# Generated by innovus_enablement/scripts/gen_innovus_lef.py from ../i3dPDK_NS3K/BE/i3dPDK_NS3K_5T_0V7_27C.lef
# Read AFTER the matching i3dPDK_NS3K_<N>T_tech.lef.
VERSION 5.8 ;
BUSBITCHARS "[]" ;
DIVIDERCHAR "/" ;





























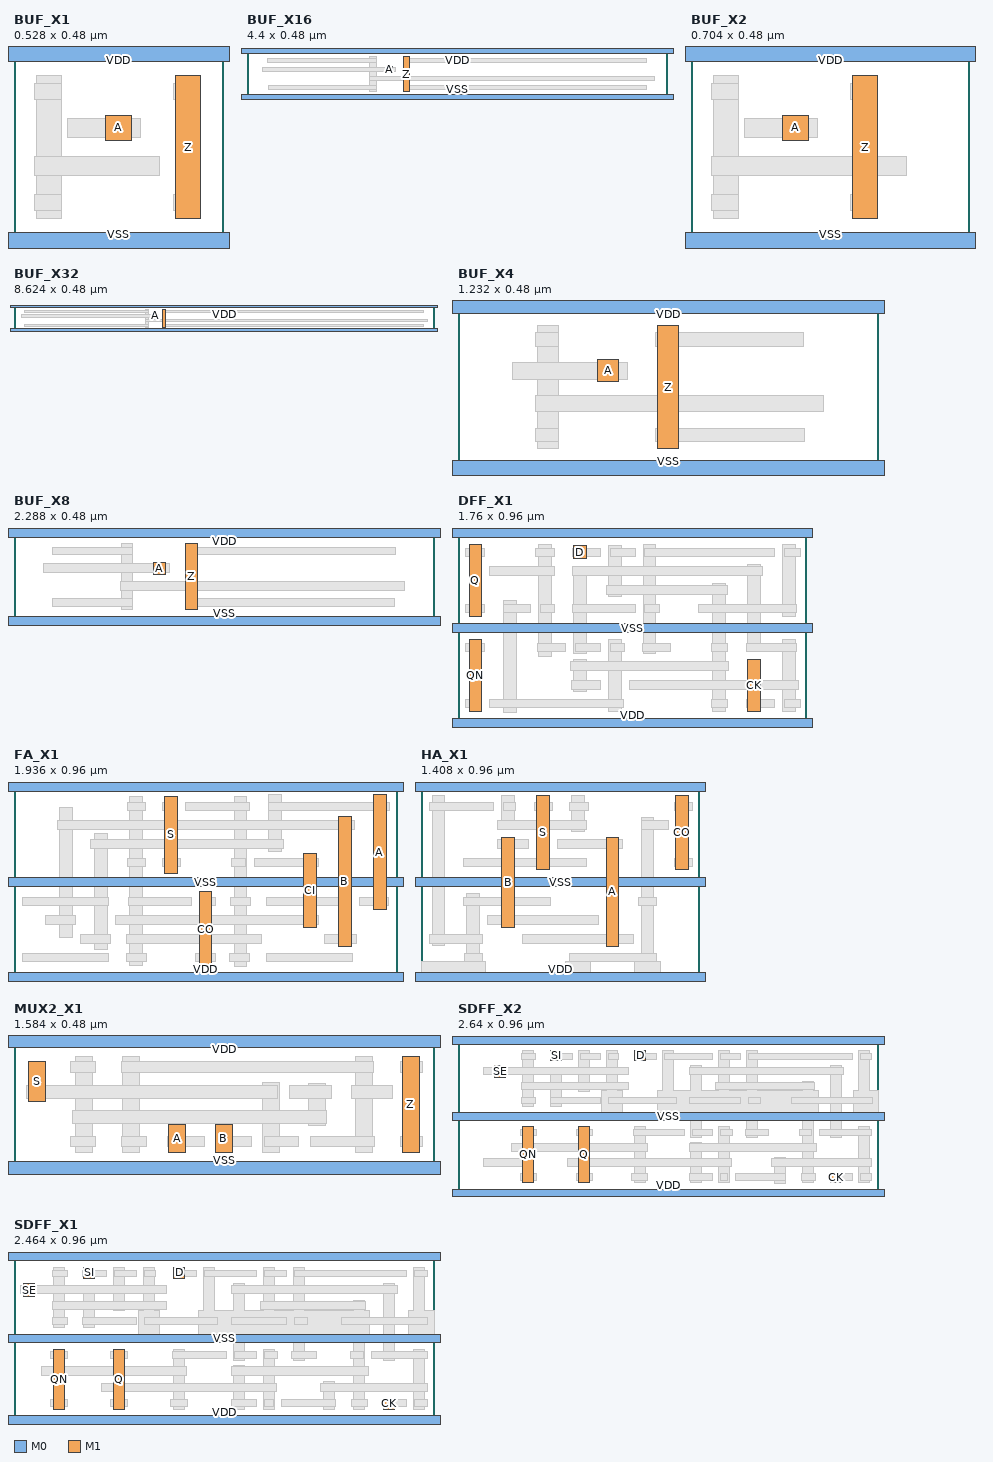
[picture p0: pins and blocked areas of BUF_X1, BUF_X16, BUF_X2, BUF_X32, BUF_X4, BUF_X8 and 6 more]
MACRO BUF_X1
  CLASS CORE ;
  ORIGIN 0 0 ;
  FOREIGN BUF_X1 0 0 ;
  SYMMETRY X Y ;
  SITE i3d_nsfet3nm ;
  SIZE 0.5280 BY 0.4800 ;
  PIN VDD
    DIRECTION INOUT ;
    USE POWER ;
    PORT
      LAYER M0 ;
        RECT -0.0640 0.4560 0.5920 0.5040 ;
    END
  END VDD
  PIN VSS
    DIRECTION INOUT ;
    USE GROUND ;
    PORT
      LAYER M0 ;
        RECT -0.0640 -0.0240 0.5920 0.0240 ;
    END
  END VSS
  PIN A
    DIRECTION INPUT ;
    USE SIGNAL ;
    PORT
      LAYER M1 ;
        RECT 0.2320 0.2560 0.2960 0.3200 ;
    END
  END A
  PIN Z
    DIRECTION OUTPUT ;
    USE SIGNAL ;
    PORT
      LAYER M1 ;
        RECT 0.4080 0.0600 0.4720 0.4200 ;
    END
  END Z
  OBS
    LAYER M1 DESIGNRULEWIDTH 0 ;
      RECT 0.0560 0.0600 0.1200 0.4200 ;
    LAYER M0 DESIGNRULEWIDTH 0 ;
      RECT 0.4040 0.0800 0.4720 0.1200 ;
      RECT 0.0520 0.0800 0.1200 0.1200 ;
      RECT 0.0520 0.1680 0.3680 0.2160 ;
      RECT 0.1360 0.2640 0.3200 0.3120 ;
      RECT 0.4040 0.3600 0.4720 0.4000 ;
      RECT 0.0520 0.3600 0.1200 0.4000 ;
  END
END BUF_X1

MACRO BUF_X16
  CLASS CORE ;
  ORIGIN 0 0 ;
  FOREIGN BUF_X16 0 0 ;
  SYMMETRY X Y ;
  SITE i3d_nsfet3nm ;
  SIZE 4.4000 BY 0.4800 ;
  PIN VDD
    DIRECTION INOUT ;
    USE POWER ;
    PORT
      LAYER M0 ;
        RECT -0.0640 0.4560 4.4640 0.5040 ;
    END
  END VDD
  PIN VSS
    DIRECTION INOUT ;
    USE GROUND ;
    PORT
      LAYER M0 ;
        RECT -0.0640 -0.0240 4.4640 0.0240 ;
    END
  END VSS
  PIN A
    DIRECTION INPUT ;
    USE SIGNAL ;
    PORT
      LAYER M1 ;
        RECT 1.4640 0.2560 1.5280 0.3200 ;
    END
  END A
  PIN Z
    DIRECTION OUTPUT ;
    USE SIGNAL ;
    PORT
      LAYER M1 ;
        RECT 1.6400 0.0600 1.7040 0.4200 ;
    END
  END Z
  OBS
    LAYER M1 DESIGNRULEWIDTH 0 ;
      RECT 1.2880 0.0600 1.3520 0.4200 ;
    LAYER M0 DESIGNRULEWIDTH 0 ;
      RECT 1.6360 0.0800 4.1840 0.1200 ;
      RECT 0.2240 0.0800 1.3520 0.1200 ;
      RECT 1.2840 0.1680 4.2640 0.2160 ;
      RECT 0.1600 0.2640 1.5520 0.3120 ;
      RECT 1.6360 0.3600 4.1880 0.4000 ;
      RECT 0.2120 0.3600 1.3520 0.4000 ;
  END
END BUF_X16

MACRO BUF_X2
  CLASS CORE ;
  ORIGIN 0 0 ;
  FOREIGN BUF_X2 0 0 ;
  SYMMETRY X Y ;
  SITE i3d_nsfet3nm ;
  SIZE 0.7040 BY 0.4800 ;
  PIN VDD
    DIRECTION INOUT ;
    USE POWER ;
    PORT
      LAYER M0 ;
        RECT -0.0640 0.4560 0.7680 0.5040 ;
    END
  END VDD
  PIN VSS
    DIRECTION INOUT ;
    USE GROUND ;
    PORT
      LAYER M0 ;
        RECT -0.0640 -0.0240 0.7680 0.0240 ;
    END
  END VSS
  PIN A
    DIRECTION INPUT ;
    USE SIGNAL ;
    PORT
      LAYER M1 ;
        RECT 0.2320 0.2560 0.2960 0.3200 ;
    END
  END A
  PIN Z
    DIRECTION OUTPUT ;
    USE SIGNAL ;
    PORT
      LAYER M1 ;
        RECT 0.4080 0.0600 0.4720 0.4200 ;
    END
  END Z
  OBS
    LAYER M1 DESIGNRULEWIDTH 0 ;
      RECT 0.0560 0.0600 0.1200 0.4200 ;
    LAYER M0 DESIGNRULEWIDTH 0 ;
      RECT 0.4040 0.0800 0.4720 0.1200 ;
      RECT 0.0520 0.0800 0.1200 0.1200 ;
      RECT 0.0520 0.1680 0.5440 0.2160 ;
      RECT 0.1360 0.2640 0.3200 0.3120 ;
      RECT 0.4040 0.3600 0.4720 0.4000 ;
      RECT 0.0520 0.3600 0.1200 0.4000 ;
  END
END BUF_X2

MACRO BUF_X32
  CLASS CORE ;
  ORIGIN 0 0 ;
  FOREIGN BUF_X32 0 0 ;
  SYMMETRY X Y ;
  SITE i3d_nsfet3nm ;
  SIZE 8.6240 BY 0.4800 ;
  PIN VDD
    DIRECTION INOUT ;
    USE POWER ;
    PORT
      LAYER M0 ;
        RECT -0.0640 0.4560 8.6880 0.5040 ;
    END
  END VDD
  PIN VSS
    DIRECTION INOUT ;
    USE GROUND ;
    PORT
      LAYER M0 ;
        RECT -0.0640 -0.0240 8.6880 0.0240 ;
    END
  END VSS
  PIN Z
    DIRECTION OUTPUT ;
    USE SIGNAL ;
    PORT
      LAYER M1 ;
        RECT 3.0480 0.0600 3.1120 0.4200 ;
    END
  END Z
  PIN A
    DIRECTION INPUT ;
    USE SIGNAL ;
    PORT
      LAYER M1 ;
        RECT 2.8720 0.2560 2.9360 0.3200 ;
    END
  END A
  OBS
    LAYER M1 DESIGNRULEWIDTH 0 ;
      RECT 2.6960 0.0600 2.7600 0.4200 ;
    LAYER M0 DESIGNRULEWIDTH 0 ;
      RECT 3.0440 0.0800 8.4160 0.1200 ;
      RECT 0.2200 0.0800 2.7600 0.1200 ;
      RECT 2.6920 0.1680 8.4920 0.2160 ;
      RECT 0.1560 0.2640 2.9600 0.3120 ;
      RECT 3.0440 0.3600 8.4040 0.4000 ;
      RECT 0.2120 0.3600 2.7600 0.4000 ;
  END
END BUF_X32

MACRO BUF_X4
  CLASS CORE ;
  ORIGIN 0 0 ;
  FOREIGN BUF_X4 0 0 ;
  SYMMETRY X Y ;
  SITE i3d_nsfet3nm ;
  SIZE 1.2320 BY 0.4800 ;
  PIN VDD
    DIRECTION INOUT ;
    USE POWER ;
    PORT
      LAYER M0 ;
        RECT -0.0640 0.4560 1.2960 0.5040 ;
    END
  END VDD
  PIN VSS
    DIRECTION INOUT ;
    USE GROUND ;
    PORT
      LAYER M0 ;
        RECT -0.0640 -0.0240 1.2960 0.0240 ;
    END
  END VSS
  PIN A
    DIRECTION INPUT ;
    USE SIGNAL ;
    PORT
      LAYER M1 ;
        RECT 0.4080 0.2560 0.4720 0.3200 ;
    END
  END A
  PIN Z
    DIRECTION OUTPUT ;
    USE SIGNAL ;
    PORT
      LAYER M1 ;
        RECT 0.5840 0.0600 0.6480 0.4200 ;
    END
  END Z
  OBS
    LAYER M1 DESIGNRULEWIDTH 0 ;
      RECT 0.2320 0.0600 0.2960 0.4200 ;
    LAYER M0 DESIGNRULEWIDTH 0 ;
      RECT 0.5800 0.0800 1.0160 0.1200 ;
      RECT 0.2280 0.0800 0.2960 0.1200 ;
      RECT 0.2280 0.1680 1.0720 0.2160 ;
      RECT 0.1600 0.2640 0.4960 0.3120 ;
      RECT 0.5800 0.3600 1.0120 0.4000 ;
      RECT 0.2280 0.3600 0.2960 0.4000 ;
  END
END BUF_X4

MACRO BUF_X8
  CLASS CORE ;
  ORIGIN 0 0 ;
  FOREIGN BUF_X8 0 0 ;
  SYMMETRY X Y ;
  SITE i3d_nsfet3nm ;
  SIZE 2.2880 BY 0.4800 ;
  PIN VDD
    DIRECTION INOUT ;
    USE POWER ;
    PORT
      LAYER M0 ;
        RECT -0.0640 0.4560 2.3520 0.5040 ;
    END
  END VDD
  PIN VSS
    DIRECTION INOUT ;
    USE GROUND ;
    PORT
      LAYER M0 ;
        RECT -0.0640 -0.0240 2.3520 0.0240 ;
    END
  END VSS
  PIN A
    DIRECTION INPUT ;
    USE SIGNAL ;
    PORT
      LAYER M1 ;
        RECT 0.7600 0.2560 0.8240 0.3200 ;
    END
  END A
  PIN Z
    DIRECTION OUTPUT ;
    USE SIGNAL ;
    PORT
      LAYER M1 ;
        RECT 0.9360 0.0600 1.0000 0.4200 ;
    END
  END Z
  OBS
    LAYER M1 DESIGNRULEWIDTH 0 ;
      RECT 0.5840 0.0600 0.6480 0.4200 ;
    LAYER M0 DESIGNRULEWIDTH 0 ;
      RECT 0.9320 0.0800 2.0720 0.1200 ;
      RECT 0.2080 0.0800 0.6480 0.1200 ;
      RECT 0.5800 0.1680 2.1280 0.2160 ;
      RECT 0.1600 0.2640 0.8480 0.3120 ;
      RECT 0.9320 0.3600 2.0760 0.4000 ;
      RECT 0.2080 0.3600 0.6480 0.4000 ;
  END
END BUF_X8

MACRO DFF_X1
  CLASS CORE ;
  ORIGIN 0 0 ;
  FOREIGN DFF_X1 0 0 ;
  SYMMETRY X Y ;
  SITE i3d_nsfet3nm_2H_VDD ;
  SIZE 1.7600 BY 0.9600 ;
  PIN Q
    DIRECTION OUTPUT ;
    USE SIGNAL ;
    PORT
      LAYER M1 ;
        RECT 0.0560 0.5400 0.1200 0.9000 ;
    END
  END Q
  PIN VDD
    DIRECTION INOUT ;
    USE POWER ;
    PORT
      LAYER M0 ;
        RECT -0.0640 0.9360 1.8240 0.9840 ;
        RECT -0.0640 -0.0240 1.8240 0.0240 ;
    END
  END VDD
  PIN VSS
    DIRECTION INOUT ;
    USE GROUND ;
    PORT
      LAYER M0 ;
        RECT -0.0640 0.4560 1.8240 0.5040 ;
    END
  END VSS
  PIN D
    DIRECTION INPUT ;
    USE SIGNAL ;
    PORT
      LAYER M1 ;
        RECT 0.5840 0.8320 0.6480 0.8960 ;
    END
  END D
  PIN QN
    DIRECTION OUTPUT ;
    USE SIGNAL ;
    PORT
      LAYER M1 ;
        RECT 0.0560 0.0600 0.1200 0.4200 ;
    END
  END QN
  PIN CK
    DIRECTION INPUT ;
    USE SIGNAL ;
    PORT
      LAYER M1 ;
        RECT 1.4640 0.0600 1.5280 0.3200 ;
    END
  END CK
  OBS
    LAYER M1 ;
      RECT 0.2320 0.0520 0.2960 0.6200 ;
      RECT 0.7600 0.0600 0.8240 0.4200 ;
      RECT 1.2880 0.0600 1.3520 0.7040 ;
      RECT 1.6400 0.0600 1.7040 0.4200 ;
      RECT 0.5840 0.1600 0.6480 0.3200 ;
      RECT 0.4080 0.3360 0.4720 0.9000 ;
      RECT 0.5840 0.3520 0.6480 0.7520 ;
      RECT 0.9360 0.3520 1.0000 0.9000 ;
      RECT 1.4640 0.4000 1.5280 0.8000 ;
      RECT 1.6400 0.5400 1.7040 0.9000 ;
      RECT 0.7600 0.6400 0.8240 0.8960 ;
    LAYER M0 ;
      RECT 0.0400 0.0800 0.1120 0.1200 ;
      RECT 0.1600 0.0800 0.8360 0.1200 ;
      RECT 1.2800 0.0800 1.3600 0.1200 ;
      RECT 1.4600 0.0800 1.6000 0.1200 ;
      RECT 1.6480 0.0800 1.7280 0.1200 ;
      RECT 0.5720 0.1680 0.7200 0.2160 ;
      RECT 0.8640 0.1680 1.7200 0.2160 ;
      RECT 0.5680 0.2640 1.3680 0.3120 ;
      RECT 0.0400 0.3600 0.1360 0.4000 ;
      RECT 0.4000 0.3600 0.5440 0.4000 ;
      RECT 0.5920 0.3600 0.7200 0.4000 ;
      RECT 0.7680 0.3600 0.8400 0.4000 ;
      RECT 0.9320 0.3600 1.0720 0.4000 ;
      RECT 1.2800 0.3600 1.3600 0.4000 ;
      RECT 1.4560 0.3600 1.7120 0.4000 ;
      RECT 0.0400 0.5600 0.1360 0.6000 ;
      RECT 0.2280 0.5600 0.3680 0.6000 ;
      RECT 0.4160 0.5600 0.4880 0.6000 ;
      RECT 0.5760 0.5600 0.8960 0.6000 ;
      RECT 0.9440 0.5600 1.0200 0.6000 ;
      RECT 1.2160 0.5600 1.7120 0.6000 ;
      RECT 0.7480 0.6480 1.3600 0.6960 ;
      RECT 0.1600 0.7440 0.4880 0.7920 ;
      RECT 0.5800 0.7440 1.5360 0.7920 ;
      RECT 0.0400 0.8400 0.1360 0.8800 ;
      RECT 0.3920 0.8400 0.4880 0.8800 ;
      RECT 0.5760 0.8400 0.7200 0.8800 ;
      RECT 0.7680 0.8400 0.8960 0.8800 ;
      RECT 0.9440 0.8400 1.6000 0.8800 ;
      RECT 1.6480 0.8400 1.7280 0.8800 ;
  END
END DFF_X1


MACRO FA_X1
  CLASS CORE ;
  ORIGIN 0 0 ;
  FOREIGN FA 0 0 ;
  SYMMETRY X Y ;
  SITE i3d_nsfet3nm_2H_VDD ;
  SIZE 1.9360 BY 0.9600 ;
  PIN VDD
    DIRECTION INOUT ;
    USE POWER ;
    PORT
      LAYER M0 ;
        RECT -0.0640 -0.0240 2.0000 0.0240 ;
        RECT -0.0640 0.9360 2.0000 0.9840 ;
    END
  END VDD
  PIN VSS
    DIRECTION INOUT ;
    USE GROUND ;
    PORT
      LAYER M0 ;
        RECT -0.0640 0.4560 2.0000 0.5040 ;
    END
  END VSS
  PIN CO
    DIRECTION OUTPUT ;
    USE SIGNAL ;
    PORT
      LAYER M1 ;
        RECT 0.9360 0.0520 1.0000 0.4320 ;
    END
  END CO
  PIN CI
    DIRECTION INPUT ;
    USE SIGNAL ;
    PORT
      LAYER M1 ;
        RECT 1.4640 0.2520 1.5280 0.6240 ;
    END
  END CI
  PIN A
    DIRECTION INPUT ;
    USE SIGNAL ;
    PORT
      LAYER M1 ;
        RECT 1.8160 0.3400 1.8800 0.9200 ;
    END
  END A
  PIN B
    DIRECTION INPUT ;
    USE SIGNAL ;
    PORT
      LAYER M1 ;
        RECT 1.6400 0.1560 1.7040 0.8120 ;
    END
  END B
  PIN S
    DIRECTION OUTPUT ;
    USE SIGNAL ;
    PORT
      LAYER M1 ;
        RECT 0.7600 0.5240 0.8240 0.9120 ;
    END
  END S
  OBS
    LAYER M1 DESIGNRULEWIDTH 0 ;
      RECT 1.1120 0.0520 1.1760 0.9120 ;
      RECT 0.5840 0.0560 0.6480 0.9120 ;
      RECT 0.4080 0.1400 0.4720 0.7240 ;
      RECT 0.2320 0.2000 0.2960 0.8560 ;
      RECT 1.2880 0.6360 1.3520 0.9200 ;
    LAYER M0 DESIGNRULEWIDTH 0 ;
      RECT 1.2760 0.0800 1.7080 0.1200 ;
      RECT 1.0880 0.0800 1.1880 0.1200 ;
      RECT 0.9160 0.0800 1.0160 0.1200 ;
      RECT 0.5680 0.0800 0.6680 0.1200 ;
      RECT 0.0440 0.0800 0.4760 0.1200 ;
      RECT 1.5680 0.1680 1.7280 0.2160 ;
      RECT 0.5680 0.1680 1.2480 0.2160 ;
      RECT 0.3360 0.1680 0.4880 0.2160 ;
      RECT 0.5120 0.2640 1.5360 0.3120 ;
      RECT 0.1600 0.2640 0.3120 0.3120 ;
      RECT 1.7440 0.3600 1.8920 0.4000 ;
      RECT 1.2760 0.3600 1.6960 0.4000 ;
      RECT 1.0960 0.3600 1.1960 0.4000 ;
      RECT 0.9440 0.3600 1.0160 0.4000 ;
      RECT 0.5760 0.3600 0.8960 0.4000 ;
      RECT 0.0440 0.3600 0.4760 0.4000 ;
      RECT 1.2160 0.5600 1.5360 0.6000 ;
      RECT 1.1000 0.5600 1.1680 0.6000 ;
      RECT 0.7480 0.5600 0.8400 0.6000 ;
      RECT 0.5720 0.5600 0.6640 0.6000 ;
      RECT 0.3880 0.6480 1.3600 0.6960 ;
      RECT 0.2200 0.7440 1.7200 0.7920 ;
      RECT 1.2840 0.8400 1.8960 0.8800 ;
      RECT 0.8640 0.8400 1.1920 0.8800 ;
      RECT 0.7480 0.8400 0.8160 0.8800 ;
      RECT 0.5720 0.8400 0.6640 0.8800 ;
  END
END FA_X1

MACRO HA_X1
  CLASS CORE ;
  ORIGIN 0 0 ;
  FOREIGN HA 0 0 ;
  SYMMETRY X Y ;
  SITE i3d_nsfet3nm_2H_VDD ;
  SIZE 1.4080 BY 0.9600 ;
  PIN VDD
    DIRECTION INOUT ;
    USE POWER ;
    PORT
      LAYER M0 ;
        RECT -0.0640 -0.0240 1.4720 0.0240 ;
        RECT -0.0640 0.9360 1.4720 0.9840 ;
    END
  END VDD
  PIN S
    DIRECTION OUTPUT ;
    USE SIGNAL ;
    PORT
      LAYER M1 ;
        RECT 0.5840 0.5440 0.6480 0.9160 ;
    END
  END S
  PIN B
    DIRECTION INPUT ;
    USE SIGNAL ;
    PORT
      LAYER M1 ;
        RECT 0.4080 0.2520 0.4720 0.7040 ;
    END
  END B
  PIN A
    DIRECTION INPUT ;
    USE SIGNAL ;
    PORT
      LAYER M1 ;
        RECT 0.9360 0.1560 1.0000 0.7040 ;
    END
  END A
  PIN VSS
    DIRECTION INOUT ;
    USE GROUND ;
    PORT
      LAYER M0 ;
        RECT -0.0640 0.4560 1.4720 0.5040 ;
    END
  END VSS
  PIN CO
    DIRECTION OUTPUT ;
    USE SIGNAL ;
    PORT
      LAYER M1 ;
        RECT 1.2880 0.5440 1.3520 0.9160 ;
    END
  END CO
  OBS
    LAYER M1 DESIGNRULEWIDTH 0 ;
      POLYGON 1.2080 0.0000 1.2080 0.0760 1.1760 0.0760 1.1760 0.8040 1.1120 0.8040 1.1120 0.0760 1.0800 0.0760 1.0800 0.0000 ;
      RECT 0.7280 0.0000 0.8560 0.0760 ;
      POLYGON 0.3280 0.0000 0.3280 0.0760 0.2960 0.0760 0.2960 0.4200 0.2320 0.4200 0.2320 0.0760 0.0000 0.0760 0.0000 0.0000 ;
      RECT 0.0560 0.1600 0.1200 0.9160 ;
      RECT 0.7600 0.7360 0.8240 0.9160 ;
      RECT 0.4080 0.7840 0.4720 0.9160 ;
    LAYER M0 DESIGNRULEWIDTH 0 ;
      RECT 0.7480 0.0800 1.1920 0.1200 ;
      RECT 0.2200 0.0800 0.3120 0.1200 ;
      RECT 0.5120 0.1680 1.0720 0.2160 ;
      RECT 0.0440 0.1680 0.3120 0.2160 ;
      RECT 0.3360 0.2640 0.8960 0.3120 ;
      RECT 1.1000 0.3600 1.1920 0.4000 ;
      RECT 0.2160 0.3600 0.6560 0.4000 ;
      RECT 1.2800 0.5600 1.3720 0.6000 ;
      RECT 0.2160 0.5600 0.8360 0.6000 ;
      RECT 0.6880 0.6480 1.0160 0.6960 ;
      RECT 0.3880 0.6480 0.5440 0.6960 ;
      RECT 1.1120 0.7440 1.2480 0.7920 ;
      RECT 0.3880 0.7440 0.8360 0.7920 ;
      RECT 1.2800 0.8400 1.3720 0.8800 ;
      RECT 0.7520 0.8400 0.8440 0.8800 ;
      RECT 0.5720 0.8400 0.6640 0.8800 ;
      RECT 0.4160 0.8400 0.4760 0.8800 ;
      RECT 0.0440 0.8400 0.3680 0.8800 ;
  END
END HA_X1

MACRO MUX2_X1
  CLASS CORE ;
  ORIGIN 0 0 ;
  FOREIGN MUX2_X1 0 0 ;
  SYMMETRY X Y ;
  SITE i3d_nsfet3nm ;
  SIZE 1.5840 BY 0.4800 ;
  PIN VDD
    DIRECTION INOUT ;
    USE POWER ;
    PORT
      LAYER M0 ;
        RECT -0.0640 0.4560 1.6480 0.5040 ;
    END
  END VDD
  PIN VSS
    DIRECTION INOUT ;
    USE GROUND ;
    PORT
      LAYER M0 ;
        RECT -0.0640 -0.0240 1.6480 0.0240 ;
    END
  END VSS
  PIN A
    DIRECTION INPUT ;
    USE SIGNAL ;
    PORT
      LAYER M1 ;
        RECT 0.5840 0.0600 0.6480 0.1640 ;
    END
  END A
  PIN B
    DIRECTION INPUT ;
    USE SIGNAL ;
    PORT
      LAYER M1 ;
        RECT 0.7600 0.0600 0.8240 0.1640 ;
    END
  END B
  PIN S
    DIRECTION INPUT ;
    USE SIGNAL ;
    PORT
      LAYER M1 ;
        RECT 0.0560 0.2520 0.1200 0.4000 ;
    END
  END S
  PIN Z
    DIRECTION OUTPUT ;
    USE SIGNAL ;
    PORT
      LAYER M1 ;
        RECT 1.4640 0.0600 1.5280 0.4200 ;
    END
  END Z
  OBS
    LAYER M1 DESIGNRULEWIDTH 0 ;
      RECT 1.2880 0.0600 1.3520 0.4200 ;
      RECT 0.9360 0.0600 1.0000 0.3240 ;
      RECT 0.4080 0.0600 0.4720 0.4200 ;
      RECT 0.2320 0.0600 0.2960 0.4200 ;
      RECT 1.1120 0.1600 1.1760 0.3200 ;
    LAYER M0 DESIGNRULEWIDTH 0 ;
      RECT 1.4560 0.0800 1.5400 0.1200 ;
      RECT 1.1200 0.0800 1.3600 0.1200 ;
      RECT 0.9440 0.0800 1.0720 0.1200 ;
      RECT 0.7680 0.0800 0.8960 0.1200 ;
      RECT 0.5800 0.0800 0.7200 0.1200 ;
      RECT 0.4040 0.0800 0.5000 0.1200 ;
      RECT 0.2120 0.0800 0.3080 0.1200 ;
      RECT 0.2200 0.1680 1.1800 0.2160 ;
      RECT 1.2720 0.2640 1.4280 0.3120 ;
      RECT 1.0400 0.2640 1.1960 0.3120 ;
      RECT 0.0480 0.2640 0.9920 0.3120 ;
      RECT 1.4560 0.3600 1.5400 0.4000 ;
      RECT 0.4040 0.3600 1.3560 0.4000 ;
      RECT 0.2120 0.3600 0.3080 0.4000 ;
  END
END MUX2_X1

MACRO SDFF_X2
  CLASS CORE ;
  ORIGIN 0 0 ;
  FOREIGN SDFF_X2 0 0 ;
  SYMMETRY X Y ;
  SITE i3d_nsfet3nm_2H_VDD ;
  SIZE 2.6400 BY 0.9600 ;
  PIN VDD
    DIRECTION INOUT ;
    USE POWER ;
    PORT
      LAYER M0 ;
        RECT -0.0640 -0.0240 2.7040 0.0240 ;
        RECT -0.0640 0.9360 2.7040 0.9840 ;
    END
  END VDD
  PIN VSS
    DIRECTION INOUT ;
    USE GROUND ;
    PORT
      LAYER M0 ;
        RECT -0.0640 0.4560 2.7040 0.5040 ;
    END
  END VSS
  PIN Q
    DIRECTION OUTPUT ;
    USE SIGNAL ;
    PORT
      LAYER M1 ;
        RECT 0.7600 0.0640 0.8240 0.4160 ;
    END
  END Q
  PIN QN
    DIRECTION OUTPUT ;
    USE SIGNAL ;
    PORT
      LAYER M1 ;
        RECT 0.4080 0.0640 0.4720 0.4160 ;
    END
  END QN
  PIN SE
    DIRECTION INPUT ;
    USE SIGNAL ;
    PORT
      LAYER M1 ;
        RECT 0.2320 0.7240 0.2960 0.8000 ;
    END
  END SE
  PIN SI
    DIRECTION INPUT ;
    USE SIGNAL ;
    PORT
      LAYER M1 ;
        RECT 0.5840 0.8320 0.6480 0.8960 ;
    END
  END SI
  PIN D
    DIRECTION INPUT ;
    USE SIGNAL ;
    PORT
      LAYER M1 ;
        RECT 1.1120 0.8320 1.1760 0.8960 ;
    END
  END D
  PIN CK
    DIRECTION INPUT ;
    USE SIGNAL ;
    PORT
      LAYER M1 ;
        RECT 2.3440 0.0640 2.4080 0.1280 ;
    END
  END CK
  OBS
    LAYER M1 DESIGNRULEWIDTH 0 ;
      RECT 1.9920 0.0600 2.0560 0.2240 ;
      RECT 1.1120 0.0640 1.1760 0.4160 ;
      RECT 1.4640 0.0640 1.5280 0.3200 ;
      RECT 1.6400 0.0640 1.7040 0.4160 ;
      POLYGON 2.2320 0.0640 2.2320 0.4960 2.2640 0.4960 2.2640 0.6440 2.2320 0.6440 2.2320 0.7040 2.1680 0.7040 2.1680 0.6440 1.8800 0.6440 1.8800 0.8960 1.8160 0.8960 1.8160 0.6440 1.7040 0.6440 1.7040 0.8960 1.6400 0.8960 1.6400 0.6440 1.5280 0.6440 1.5280 0.8000 1.4640 0.8000 1.4640 0.6440 1.3520 0.6440 1.3520 0.8960 1.2880 0.8960 1.2880 0.6440 1.2560 0.6440 1.2560 0.4960 1.4640 0.4960 1.4640 0.3520 1.5280 0.3520 1.5280 0.4960 1.8160 0.4960 1.8160 0.3520 1.8800 0.3520 1.8800 0.4960 2.1680 0.4960 2.1680 0.0640 ;
      RECT 2.5200 0.0640 2.5840 0.4160 ;
      RECT 2.3440 0.3520 2.4080 0.8000 ;
      POLYGON 1.0320 0.4960 1.0320 0.6440 1.0000 0.6440 1.0000 0.8960 0.9360 0.8960 0.9360 0.6440 0.9040 0.6440 0.9040 0.4960 ;
      POLYGON 2.6400 0.4960 2.6400 0.6440 2.5840 0.6440 2.5840 0.8960 2.5200 0.8960 2.5200 0.6440 2.4880 0.6440 2.4880 0.4960 ;
      RECT 0.4080 0.5440 0.4720 0.8960 ;
      RECT 0.5840 0.5440 0.6480 0.7520 ;
      RECT 0.7600 0.6400 0.8240 0.8960 ;
    LAYER M0 DESIGNRULEWIDTH 0 ;
      RECT 0.3920 0.0800 0.4920 0.1200 ;
      RECT 0.7440 0.0800 0.8440 0.1200 ;
      RECT 1.0920 0.0800 1.1920 0.1200 ;
      RECT 1.4520 0.0800 1.6000 0.1200 ;
      RECT 1.6480 0.0800 1.6960 0.1200 ;
      RECT 1.7440 0.0800 2.0600 0.1200 ;
      RECT 2.1560 0.0800 2.2480 0.1200 ;
      RECT 2.3320 0.0800 2.4800 0.1200 ;
      RECT 2.5280 0.0800 2.6000 0.1200 ;
      RECT 0.1600 0.1680 0.4240 0.2160 ;
      RECT 0.6880 0.1680 1.7160 0.2160 ;
      RECT 1.9720 0.1680 2.6000 0.2160 ;
      RECT 0.3360 0.2640 1.1880 0.3120 ;
      RECT 1.4520 0.2640 2.2560 0.3120 ;
      RECT 0.3920 0.3600 0.4920 0.4000 ;
      RECT 0.7440 0.3600 0.8440 0.4000 ;
      RECT 1.1040 0.3600 1.4240 0.4000 ;
      RECT 1.4720 0.3600 1.6000 0.4000 ;
      RECT 1.6480 0.3600 1.7240 0.4000 ;
      RECT 1.8040 0.3600 1.9520 0.4000 ;
      RECT 2.1480 0.3600 2.2240 0.4000 ;
      RECT 2.2720 0.3600 2.6000 0.4000 ;
      RECT 0.4000 0.5600 0.4880 0.6000 ;
      RECT 0.5800 0.5600 0.8960 0.6000 ;
      RECT 0.9440 0.5600 1.3720 0.6000 ;
      RECT 1.4520 0.5600 1.7760 0.6000 ;
      RECT 1.8240 0.5600 1.9000 0.6000 ;
      RECT 2.0960 0.5600 2.6040 0.6000 ;
      RECT 0.4000 0.6480 1.0720 0.6960 ;
      RECT 1.6200 0.6480 2.2400 0.6960 ;
      RECT 0.1600 0.7440 1.0720 0.7920 ;
      RECT 1.4520 0.7440 2.4240 0.7920 ;
      RECT 0.4000 0.8400 0.4880 0.8800 ;
      RECT 0.5800 0.8400 0.7200 0.8800 ;
      RECT 0.7680 0.8400 0.8960 0.8800 ;
      RECT 0.9440 0.8400 1.0080 0.8800 ;
      RECT 1.1200 0.8400 1.2480 0.8800 ;
      RECT 1.2960 0.8400 1.6000 0.8800 ;
      RECT 1.6480 0.8400 1.7760 0.8800 ;
      RECT 1.8240 0.8400 2.4800 0.8800 ;
      RECT 2.5280 0.8400 2.6000 0.8800 ;
  END
END SDFF_X2

MACRO SDFF_X1
  CLASS CORE ;
  ORIGIN 0 0 ;
  FOREIGN SDFF_X1 0 0 ;
  SYMMETRY X Y ;
  SITE i3d_nsfet3nm_2H_VDD ;
  SIZE 2.4640 BY 0.9600 ;
  PIN VDD
    DIRECTION INOUT ;
    USE POWER ;
    PORT
      LAYER M0 ;
        RECT -0.0640 -0.0240 2.5280 0.0240 ;
        RECT -0.0640 0.9360 2.5280 0.9840 ;
    END
  END VDD
  PIN VSS
    DIRECTION INOUT ;
    USE GROUND ;
    PORT
      LAYER M0 ;
        RECT -0.0640 0.4560 2.5280 0.5040 ;
    END
  END VSS
  PIN Q
    DIRECTION OUTPUT ;
    USE SIGNAL ;
    PORT
      LAYER M1 ;
        RECT 0.5840 0.0640 0.6480 0.4160 ;
    END
  END Q
  PIN QN
    DIRECTION OUTPUT ;
    USE SIGNAL ;
    PORT
      LAYER M1 ;
        RECT 0.2320 0.0640 0.2960 0.4160 ;
    END
  END QN
  PIN SE
    DIRECTION INPUT ;
    USE SIGNAL ;
    PORT
      LAYER M1 ;
        RECT 0.0560 0.7240 0.1200 0.8000 ;
    END
  END SE
  PIN SI
    DIRECTION INPUT ;
    USE SIGNAL ;
    PORT
      LAYER M1 ;
        RECT 0.4080 0.8320 0.4720 0.8960 ;
    END
  END SI
  PIN D
    DIRECTION INPUT ;
    USE SIGNAL ;
    PORT
      LAYER M1 ;
        RECT 0.9360 0.8320 1.0000 0.8960 ;
    END
  END D
  PIN CK
    DIRECTION INPUT ;
    USE SIGNAL ;
    PORT
      LAYER M1 ;
        RECT 2.1680 0.0640 2.2320 0.1280 ;
    END
  END CK
  OBS
    LAYER M1 DESIGNRULEWIDTH 0 ;
      RECT 1.8160 0.0600 1.8800 0.2240 ;
      RECT 2.3440 0.0640 2.4080 0.4160 ;
      POLYGON 2.0560 0.0640 2.0560 0.4960 2.0880 0.4960 2.0880 0.6440 2.0560 0.6440 2.0560 0.7040 1.9920 0.7040 1.9920 0.6440 1.7040 0.6440 1.7040 0.8960 1.6400 0.8960 1.6400 0.6440 1.5280 0.6440 1.5280 0.8960 1.4640 0.8960 1.4640 0.6440 1.3520 0.6440 1.3520 0.8000 1.2880 0.8000 1.2880 0.6440 1.1760 0.6440 1.1760 0.8960 1.1120 0.8960 1.1120 0.6440 1.0800 0.6440 1.0800 0.4960 1.2880 0.4960 1.2880 0.3520 1.3520 0.3520 1.3520 0.4960 1.6400 0.4960 1.6400 0.3520 1.7040 0.3520 1.7040 0.4960 1.9920 0.4960 1.9920 0.0640 ;
      RECT 1.4640 0.0640 1.5280 0.4160 ;
      RECT 1.2880 0.0640 1.3520 0.3200 ;
      RECT 0.9360 0.0640 1.0000 0.4160 ;
      RECT 2.1680 0.3520 2.2320 0.8000 ;
      POLYGON 2.4640 0.4960 2.4640 0.6440 2.4080 0.6440 2.4080 0.8960 2.3440 0.8960 2.3440 0.6440 2.3120 0.6440 2.3120 0.4960 ;
      POLYGON 0.8560 0.4960 0.8560 0.6440 0.8240 0.6440 0.8240 0.8960 0.7600 0.8960 0.7600 0.6440 0.7280 0.6440 0.7280 0.4960 ;
      RECT 0.4080 0.5440 0.4720 0.7520 ;
      RECT 0.2320 0.5440 0.2960 0.8960 ;
      RECT 0.5840 0.6400 0.6480 0.8960 ;
    LAYER M0 DESIGNRULEWIDTH 0 ;
      RECT 2.3520 0.0800 2.4240 0.1200 ;
      RECT 2.1560 0.0800 2.3040 0.1200 ;
      RECT 1.9800 0.0800 2.0720 0.1200 ;
      RECT 1.5680 0.0800 1.8840 0.1200 ;
      RECT 1.4720 0.0800 1.5200 0.1200 ;
      RECT 1.2760 0.0800 1.4240 0.1200 ;
      RECT 0.9160 0.0800 1.0160 0.1200 ;
      RECT 0.5680 0.0800 0.6680 0.1200 ;
      RECT 0.2160 0.0800 0.3160 0.1200 ;
      RECT 1.7960 0.1680 2.4240 0.2160 ;
      RECT 0.5120 0.1680 1.5400 0.2160 ;
      RECT 1.2760 0.2640 2.0800 0.3120 ;
      RECT 0.1600 0.2640 1.0120 0.3120 ;
      RECT 2.0960 0.3600 2.4240 0.4000 ;
      RECT 1.9720 0.3600 2.0480 0.4000 ;
      RECT 1.6280 0.3600 1.7760 0.4000 ;
      RECT 1.4720 0.3600 1.5480 0.4000 ;
      RECT 1.2960 0.3600 1.4240 0.4000 ;
      RECT 0.9280 0.3600 1.2480 0.4000 ;
      RECT 0.5680 0.3600 0.6680 0.4000 ;
      RECT 0.2160 0.3600 0.3160 0.4000 ;
      RECT 1.9200 0.5600 2.4280 0.6000 ;
      RECT 1.6480 0.5600 1.7240 0.6000 ;
      RECT 1.2760 0.5600 1.6000 0.6000 ;
      RECT 0.7680 0.5600 1.1960 0.6000 ;
      RECT 0.4040 0.5600 0.7200 0.6000 ;
      RECT 0.2240 0.5600 0.3120 0.6000 ;
      RECT 1.4440 0.6480 2.0640 0.6960 ;
      RECT 0.2240 0.6480 0.8960 0.6960 ;
      RECT 1.2760 0.7440 2.2480 0.7920 ;
      RECT 0.0400 0.7440 0.8960 0.7920 ;
      RECT 2.3520 0.8400 2.4240 0.8800 ;
      RECT 1.6480 0.8400 2.3040 0.8800 ;
      RECT 1.4720 0.8400 1.6000 0.8800 ;
      RECT 1.1200 0.8400 1.4240 0.8800 ;
      RECT 0.9440 0.8400 1.0720 0.8800 ;
      RECT 0.7680 0.8400 0.8320 0.8800 ;
      RECT 0.5920 0.8400 0.7200 0.8800 ;
      RECT 0.4040 0.8400 0.5440 0.8800 ;
      RECT 0.2240 0.8400 0.3120 0.8800 ;
  END
END SDFF_X1

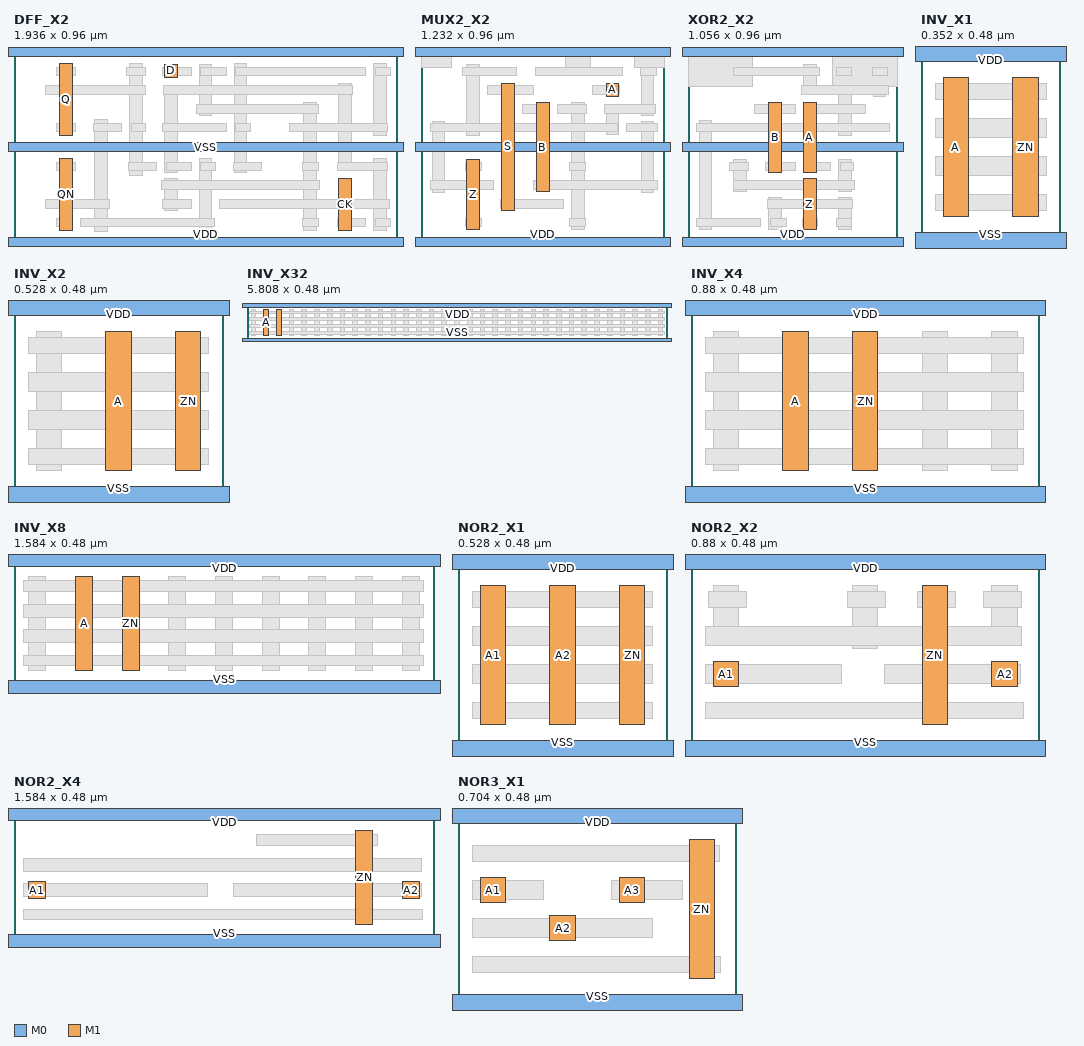
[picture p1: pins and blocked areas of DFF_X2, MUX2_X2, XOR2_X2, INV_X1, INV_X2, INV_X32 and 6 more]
MACRO DFF_X2
  CLASS CORE ;
  ORIGIN 0 0 ;
  FOREIGN DFF_X2 0 0 ;
  SYMMETRY X Y ;
  SITE i3d_nsfet3nm_2H_VDD ;
  SIZE 1.9360 BY 0.9600 ;
  PIN VDD
    DIRECTION INOUT ;
    USE POWER ;
    PORT
      LAYER M0 ;
        RECT -0.0640 -0.0240 2.0000 0.0240 ;
        RECT -0.0640 0.9360 2.0000 0.9840 ;
    END
  END VDD
  PIN VSS
    DIRECTION INOUT ;
    USE GROUND ;
    PORT
      LAYER M0 ;
        RECT -0.0640 0.4560 2.0000 0.5040 ;
    END
  END VSS
  PIN QN
    DIRECTION OUTPUT ;
    USE SIGNAL ;
    PORT
      LAYER M1 ;
        RECT 0.2320 0.0600 0.2960 0.4200 ;
    END
  END QN
  PIN Q
    DIRECTION OUTPUT ;
    USE SIGNAL ;
    PORT
      LAYER M1 ;
        RECT 0.2320 0.5400 0.2960 0.9000 ;
    END
  END Q
  PIN CK
    DIRECTION INPUT ;
    USE SIGNAL ;
    PORT
      LAYER M1 ;
        RECT 1.6400 0.0600 1.7040 0.3200 ;
    END
  END CK
  PIN D
    DIRECTION INPUT ;
    USE SIGNAL ;
    PORT
      LAYER M1 ;
        RECT 0.7600 0.8320 0.8240 0.8960 ;
    END
  END D
  OBS
    LAYER M1 DESIGNRULEWIDTH 0 ;
      RECT 0.4080 0.0520 0.4720 0.6200 ;
      RECT 1.8160 0.0600 1.8800 0.4200 ;
      RECT 1.4640 0.0600 1.5280 0.7040 ;
      RECT 0.9360 0.0600 1.0000 0.4200 ;
      RECT 0.7600 0.1600 0.8240 0.3200 ;
      RECT 0.5840 0.3360 0.6480 0.9000 ;
      RECT 1.1120 0.3520 1.1760 0.9000 ;
      RECT 0.7600 0.3520 0.8240 0.7520 ;
      RECT 1.6400 0.4000 1.7040 0.8000 ;
      RECT 1.8160 0.5400 1.8800 0.9000 ;
      RECT 0.9360 0.6400 1.0000 0.8960 ;
    LAYER M0 DESIGNRULEWIDTH 0 ;
      RECT 1.8240 0.0800 1.9040 0.1200 ;
      RECT 1.6360 0.0800 1.7760 0.1200 ;
      RECT 1.4560 0.0800 1.5360 0.1200 ;
      RECT 0.3360 0.0800 1.0120 0.1200 ;
      RECT 0.2160 0.0800 0.2880 0.1200 ;
      RECT 1.0400 0.1680 1.8960 0.2160 ;
      RECT 0.7480 0.1680 0.8960 0.2160 ;
      RECT 0.1600 0.1680 0.4840 0.2160 ;
      RECT 0.7440 0.2640 1.5440 0.3120 ;
      RECT 1.6320 0.3600 1.8880 0.4000 ;
      RECT 1.4560 0.3600 1.5360 0.4000 ;
      RECT 1.1080 0.3600 1.2480 0.4000 ;
      RECT 0.9440 0.3600 1.0160 0.4000 ;
      RECT 0.7680 0.3600 0.8960 0.4000 ;
      RECT 0.5760 0.3600 0.7200 0.4000 ;
      RECT 0.2160 0.3600 0.3120 0.4000 ;
      RECT 1.3920 0.5600 1.8880 0.6000 ;
      RECT 1.1200 0.5600 1.1960 0.6000 ;
      RECT 0.7520 0.5600 1.0720 0.6000 ;
      RECT 0.5920 0.5600 0.6640 0.6000 ;
      RECT 0.4040 0.5600 0.5440 0.6000 ;
      RECT 0.2160 0.5600 0.3120 0.6000 ;
      RECT 0.9240 0.6480 1.5360 0.6960 ;
      RECT 0.7560 0.7440 1.7120 0.7920 ;
      RECT 0.1600 0.7440 0.6640 0.7920 ;
      RECT 1.8240 0.8400 1.9040 0.8800 ;
      RECT 1.1200 0.8400 1.7760 0.8800 ;
      RECT 0.9440 0.8400 1.0720 0.8800 ;
      RECT 0.7520 0.8400 0.8960 0.8800 ;
      RECT 0.5680 0.8400 0.6640 0.8800 ;
      RECT 0.2160 0.8400 0.3120 0.8800 ;
  END
END DFF_X2

MACRO MUX2_X2
  CLASS CORE ;
  ORIGIN 0 0 ;
  FOREIGN MUX2_X2 0 0 ;
  SYMMETRY X Y ;
  SITE i3d_nsfet3nm_2H_VDD ;
  SIZE 1.2320 BY 0.9600 ;
  PIN VDD
    DIRECTION INOUT ;
    USE POWER ;
    PORT
      LAYER M0 ;
        RECT -0.0640 -0.0240 1.2960 0.0240 ;
        RECT -0.0640 0.9360 1.2960 0.9840 ;
    END
  END VDD
  PIN VSS
    DIRECTION INOUT ;
    USE GROUND ;
    PORT
      LAYER M0 ;
        RECT -0.0640 0.4560 1.2960 0.5040 ;
    END
  END VSS
  PIN Z
    DIRECTION OUTPUT ;
    USE SIGNAL ;
    PORT
      LAYER M1 ;
        RECT 0.2320 0.0640 0.2960 0.4160 ;
    END
  END Z
  PIN S
    DIRECTION INPUT ;
    USE SIGNAL ;
    PORT
      LAYER M1 ;
        RECT 0.4080 0.1600 0.4720 0.8000 ;
    END
  END S
  PIN B
    DIRECTION INPUT ;
    USE SIGNAL ;
    PORT
      LAYER M1 ;
        RECT 0.5840 0.2560 0.6480 0.7040 ;
    END
  END B
  PIN A
    DIRECTION INPUT ;
    USE SIGNAL ;
    PORT
      LAYER M1 ;
        RECT 0.9360 0.7360 1.0000 0.8000 ;
    END
  END A
  OBS
    LAYER M1 DESIGNRULEWIDTH 0 ;
      RECT 0.7600 0.0640 0.8240 0.7040 ;
      RECT 0.0560 0.2480 0.1200 0.6080 ;
      RECT 1.1120 0.2520 1.1760 0.6080 ;
      RECT 0.2320 0.5360 0.2960 0.8960 ;
      RECT 0.9360 0.5440 1.0000 0.6560 ;
      POLYGON 1.1760 0.6400 1.1760 0.8800 1.2320 0.8800 1.2320 0.9600 1.0800 0.9600 1.0800 0.8800 1.1120 0.8800 1.1120 0.6400 ;
      RECT 0.7280 0.8800 0.8560 0.9600 ;
      RECT 0.0000 0.8800 0.1520 0.9600 ;
    LAYER M0 DESIGNRULEWIDTH 0 ;
      RECT 0.7520 0.0800 0.8320 0.1200 ;
      RECT 0.2240 0.0800 0.3040 0.1200 ;
      RECT 0.4040 0.1680 0.7200 0.2160 ;
      RECT 0.5680 0.2640 1.1960 0.3120 ;
      RECT 0.0480 0.2640 0.3680 0.3120 ;
      RECT 0.7520 0.3600 0.8320 0.4000 ;
      RECT 0.2240 0.3600 0.3040 0.4000 ;
      RECT 1.0400 0.5600 1.1960 0.6000 ;
      RECT 0.0480 0.5600 0.9920 0.6000 ;
      RECT 0.9280 0.6480 1.1840 0.6960 ;
      RECT 0.6880 0.6480 0.8360 0.6960 ;
      RECT 0.5120 0.6480 0.6400 0.6960 ;
      RECT 0.8640 0.7440 1.0040 0.7920 ;
      RECT 0.3360 0.7440 0.5680 0.7920 ;
      RECT 1.1080 0.8400 1.1880 0.8800 ;
      RECT 0.5800 0.8400 1.0160 0.8800 ;
      RECT 0.2080 0.8400 0.4840 0.8800 ;
  END
END MUX2_X2

MACRO XOR2_X2
  CLASS CORE ;
  ORIGIN 0 0 ;
  FOREIGN XOR_X2 0 0 ;
  SYMMETRY X Y ;
  SITE i3d_nsfet3nm_2H_VDD ;
  SIZE 1.0560 BY 0.9600 ;
  PIN VDD
    DIRECTION INOUT ;
    USE POWER ;
    PORT
      LAYER M0 ;
        RECT -0.0640 -0.0240 1.1200 0.0240 ;
        RECT -0.0640 0.9360 1.1200 0.9840 ;
    END
  END VDD
  PIN VSS
    DIRECTION INOUT ;
    USE GROUND ;
    PORT
      LAYER M0 ;
        RECT -0.0640 0.4560 1.1200 0.5040 ;
    END
  END VSS
  PIN Z
    DIRECTION OUTPUT ;
    USE SIGNAL ;
    PORT
      LAYER M1 ;
        RECT 0.5840 0.0640 0.6480 0.3200 ;
    END
  END Z
  PIN A
    DIRECTION INPUT ;
    USE SIGNAL ;
    PORT
      LAYER M1 ;
        RECT 0.5840 0.3520 0.6480 0.7040 ;
    END
  END A
  PIN B
    DIRECTION INPUT ;
    USE SIGNAL ;
    PORT
      LAYER M1 ;
        RECT 0.4080 0.3520 0.4720 0.7040 ;
    END
  END B
  OBS
    LAYER M1 DESIGNRULEWIDTH 0 ;
      RECT 0.7600 0.0640 0.8240 0.2240 ;
      RECT 0.4080 0.0640 0.4720 0.2240 ;
      RECT 0.0560 0.0640 0.1200 0.6160 ;
      RECT 0.7600 0.2560 0.8240 0.4160 ;
      RECT 0.2320 0.2560 0.2960 0.4160 ;
      POLYGON 0.8240 0.5400 0.8240 0.7840 0.9360 0.7840 0.9360 0.7360 1.0000 0.7360 1.0000 0.7840 1.0560 0.7840 1.0560 0.9600 0.7280 0.9600 0.7280 0.7840 0.7600 0.7840 0.7600 0.5400 ;
      RECT 0.5840 0.7840 0.6480 0.8960 ;
      RECT 0.0000 0.7840 0.3280 0.9600 ;
    LAYER M0 DESIGNRULEWIDTH 0 ;
      RECT 0.7480 0.0800 0.8280 0.1200 ;
      RECT 0.5760 0.0800 0.6560 0.1200 ;
      RECT 0.4160 0.0800 0.4960 0.1200 ;
      RECT 0.0440 0.0800 0.3680 0.1200 ;
      RECT 0.4040 0.1680 0.8320 0.2160 ;
      RECT 0.2320 0.2640 0.8400 0.3120 ;
      RECT 0.7680 0.3600 0.8360 0.4000 ;
      RECT 0.5920 0.3600 0.7200 0.4000 ;
      RECT 0.3920 0.3600 0.5440 0.4000 ;
      RECT 0.2080 0.3600 0.3080 0.4000 ;
      RECT 0.0440 0.5600 1.0200 0.6000 ;
      RECT 0.5920 0.6480 0.8960 0.6960 ;
      RECT 0.3360 0.6480 0.5440 0.6960 ;
      RECT 0.5720 0.7440 1.0120 0.7920 ;
      RECT 0.9320 0.8400 1.0080 0.8800 ;
      RECT 0.7520 0.8400 0.8280 0.8800 ;
      RECT 0.2280 0.8400 0.6640 0.8800 ;
  END
END XOR2_X2

MACRO INV_X1
  CLASS CORE ;
  ORIGIN 0 0 ;
  FOREIGN INV_X1 0 0 ;
  SYMMETRY X Y ;
  SITE i3d_nsfet3nm ;
  SIZE 0.3520 BY 0.4800 ;
  PIN VDD
    DIRECTION INOUT ;
    USE POWER ;
    PORT
      LAYER M0 ;
        RECT -0.0640 0.4560 0.4160 0.5040 ;
    END
  END VDD
  PIN VSS
    DIRECTION INOUT ;
    USE GROUND ;
    PORT
      LAYER M0 ;
        RECT -0.0640 -0.0240 0.4160 0.0240 ;
    END
  END VSS
  PIN A
    DIRECTION INPUT ;
    USE SIGNAL ;
    PORT
      LAYER M1 ;
        RECT 0.0560 0.0640 0.1200 0.4160 ;
    END
  END A
  PIN ZN
    DIRECTION OUTPUT ;
    USE SIGNAL ;
    PORT
      LAYER M1 ;
        RECT 0.2320 0.0640 0.2960 0.4160 ;
    END
  END ZN
  OBS
    LAYER M0 DESIGNRULEWIDTH 0 ;
      RECT 0.0360 0.0800 0.3160 0.1200 ;
      RECT 0.0360 0.1680 0.3160 0.2160 ;
      RECT 0.0360 0.2640 0.3160 0.3120 ;
      RECT 0.0360 0.3600 0.3160 0.4000 ;
  END
END INV_X1


MACRO INV_X2
  CLASS CORE ;
  ORIGIN 0 0 ;
  FOREIGN INV_X2 0 0 ;
  SYMMETRY X Y ;
  SITE i3d_nsfet3nm ;
  SIZE 0.5280 BY 0.4800 ;
  PIN VDD
    DIRECTION INOUT ;
    USE POWER ;
    PORT
      LAYER M0 ;
        RECT -0.0640 0.4560 0.5920 0.5040 ;
    END
  END VDD
  PIN A
    DIRECTION INPUT ;
    USE SIGNAL ;
    PORT
      LAYER M1 ;
        RECT 0.2320 0.0640 0.2960 0.4160 ;
    END
  END A
  PIN ZN
    DIRECTION OUTPUT ;
    USE SIGNAL ;
    PORT
      LAYER M1 ;
        RECT 0.4080 0.0640 0.4720 0.4160 ;
    END
  END ZN
  PIN VSS
    DIRECTION INOUT ;
    USE GROUND ;
    PORT
      LAYER M0 ;
        RECT -0.0640 -0.0240 0.5920 0.0240 ;
    END
  END VSS
  OBS
    LAYER M1 DESIGNRULEWIDTH 0 ;
      RECT 0.0560 0.0640 0.1200 0.4160 ;
    LAYER M0 DESIGNRULEWIDTH 0 ;
      RECT 0.0360 0.0800 0.4920 0.1200 ;
      RECT 0.0360 0.1680 0.4920 0.2160 ;
      RECT 0.0360 0.2640 0.4920 0.3120 ;
      RECT 0.0360 0.3600 0.4920 0.4000 ;
  END
END INV_X2

MACRO INV_X32
  CLASS CORE ;
  ORIGIN 0 0 ;
  FOREIGN INV_X32 0 0 ;
  SYMMETRY X Y ;
  SITE i3d_nsfet3nm ;
  SIZE 5.8080 BY 0.4800 ;
  PIN VDD
    DIRECTION INOUT ;
    USE POWER ;
    PORT
      LAYER M0 ;
        RECT -0.0640 0.4560 5.8720 0.5040 ;
    END
  END VDD
  PIN VSS
    DIRECTION INOUT ;
    USE GROUND ;
    PORT
      LAYER M0 ;
        RECT -0.0640 -0.0240 5.8720 0.0240 ;
    END
  END VSS
  PIN A
    DIRECTION INPUT ;
    USE SIGNAL ;
    PORT
      LAYER M1 ;
        RECT 0.2320 0.0640 0.2960 0.4160 ;
    END
  END A
  PIN ZN
    DIRECTION OUTPUT ;
    USE SIGNAL ;
    PORT
      LAYER M1 ;
        RECT 0.4080 0.0640 0.4720 0.4160 ;
    END
  END ZN
  OBS
    LAYER M1 DESIGNRULEWIDTH 0 ;
      RECT 5.6880 0.0640 5.7520 0.4160 ;
      RECT 5.5120 0.0640 5.5760 0.4160 ;
      RECT 5.3360 0.0640 5.4000 0.4160 ;
      RECT 5.1600 0.0640 5.2240 0.4160 ;
      RECT 4.9840 0.0640 5.0480 0.4160 ;
      RECT 4.8080 0.0640 4.8720 0.4160 ;
      RECT 4.6320 0.0640 4.6960 0.4160 ;
      RECT 4.4560 0.0640 4.5200 0.4160 ;
      RECT 4.2800 0.0640 4.3440 0.4160 ;
      RECT 4.1040 0.0640 4.1680 0.4160 ;
      RECT 3.9280 0.0640 3.9920 0.4160 ;
      RECT 3.7520 0.0640 3.8160 0.4160 ;
      RECT 3.5760 0.0640 3.6400 0.4160 ;
      RECT 3.4000 0.0640 3.4640 0.4160 ;
      RECT 3.2240 0.0640 3.2880 0.4160 ;
      RECT 3.0480 0.0640 3.1120 0.4160 ;
      RECT 2.8720 0.0640 2.9360 0.4160 ;
      RECT 2.6960 0.0640 2.7600 0.4160 ;
      RECT 2.5200 0.0640 2.5840 0.4160 ;
      RECT 2.3440 0.0640 2.4080 0.4160 ;
      RECT 2.1680 0.0640 2.2320 0.4160 ;
      RECT 1.9920 0.0640 2.0560 0.4160 ;
      RECT 1.8160 0.0640 1.8800 0.4160 ;
      RECT 1.6400 0.0640 1.7040 0.4160 ;
      RECT 1.4640 0.0640 1.5280 0.4160 ;
      RECT 1.2880 0.0640 1.3520 0.4160 ;
      RECT 1.1120 0.0640 1.1760 0.4160 ;
      RECT 0.9360 0.0640 1.0000 0.4160 ;
      RECT 0.7600 0.0640 0.8240 0.4160 ;
      RECT 0.5840 0.0640 0.6480 0.4160 ;
      RECT 0.0560 0.0640 0.1200 0.4160 ;
    LAYER M0 DESIGNRULEWIDTH 0 ;
      RECT 0.0360 0.0800 5.7680 0.1200 ;
      RECT 0.0360 0.1680 5.7680 0.2160 ;
      RECT 0.0360 0.2640 5.7680 0.3120 ;
      RECT 0.0360 0.3600 5.7680 0.4000 ;
  END
END INV_X32



MACRO INV_X4
  CLASS CORE ;
  ORIGIN 0 0 ;
  FOREIGN INV_X4 0 0 ;
  SYMMETRY X Y ;
  SITE i3d_nsfet3nm ;
  SIZE 0.8800 BY 0.4800 ;
  PIN VDD
    DIRECTION INOUT ;
    USE POWER ;
    PORT
      LAYER M0 ;
        RECT -0.0640 0.4560 0.9440 0.5040 ;
    END
  END VDD
  PIN A
    DIRECTION INPUT ;
    USE SIGNAL ;
    PORT
      LAYER M1 ;
        RECT 0.2320 0.0640 0.2960 0.4160 ;
    END
  END A
  PIN ZN
    DIRECTION OUTPUT ;
    USE SIGNAL ;
    PORT
      LAYER M1 ;
        RECT 0.4080 0.0640 0.4720 0.4160 ;
    END
  END ZN
  PIN VSS
    DIRECTION INOUT ;
    USE GROUND ;
    PORT
      LAYER M0 ;
        RECT -0.0640 -0.0240 0.9440 0.0240 ;
    END
  END VSS
  OBS
    LAYER M1 DESIGNRULEWIDTH 0 ;
      RECT 0.7600 0.0640 0.8240 0.4160 ;
      RECT 0.5840 0.0640 0.6480 0.4160 ;
      RECT 0.0560 0.0640 0.1200 0.4160 ;
    LAYER M0 DESIGNRULEWIDTH 0 ;
      RECT 0.0360 0.0800 0.8400 0.1200 ;
      RECT 0.0360 0.1680 0.8400 0.2160 ;
      RECT 0.0360 0.2640 0.8400 0.3120 ;
      RECT 0.0360 0.3600 0.8400 0.4000 ;
  END
END INV_X4

MACRO INV_X8
  CLASS CORE ;
  ORIGIN 0 0 ;
  FOREIGN INV_X8 0 0 ;
  SYMMETRY X Y ;
  SITE i3d_nsfet3nm ;
  SIZE 1.5840 BY 0.4800 ;
  PIN VDD
    DIRECTION INOUT ;
    USE POWER ;
    PORT
      LAYER M0 ;
        RECT -0.0640 0.4560 1.6480 0.5040 ;
    END
  END VDD
  PIN A
    DIRECTION INPUT ;
    USE SIGNAL ;
    PORT
      LAYER M1 ;
        RECT 0.2320 0.0640 0.2960 0.4160 ;
    END
  END A
  PIN ZN
    DIRECTION OUTPUT ;
    USE SIGNAL ;
    PORT
      LAYER M1 ;
        RECT 0.4080 0.0640 0.4720 0.4160 ;
    END
  END ZN
  PIN VSS
    DIRECTION INOUT ;
    USE GROUND ;
    PORT
      LAYER M0 ;
        RECT -0.0640 -0.0240 1.6480 0.0240 ;
    END
  END VSS
  OBS
    LAYER M1 DESIGNRULEWIDTH 0 ;
      RECT 1.4640 0.0640 1.5280 0.4160 ;
      RECT 1.2880 0.0640 1.3520 0.4160 ;
      RECT 1.1120 0.0640 1.1760 0.4160 ;
      RECT 0.9360 0.0640 1.0000 0.4160 ;
      RECT 0.7600 0.0640 0.8240 0.4160 ;
      RECT 0.5840 0.0640 0.6480 0.4160 ;
      RECT 0.0560 0.0640 0.1200 0.4160 ;
    LAYER M0 DESIGNRULEWIDTH 0 ;
      RECT 0.0360 0.0800 1.5440 0.1200 ;
      RECT 0.0360 0.1680 1.5440 0.2160 ;
      RECT 0.0360 0.2640 1.5440 0.3120 ;
      RECT 0.0360 0.3600 1.5440 0.4000 ;
  END
END INV_X8

MACRO NOR2_X1
  CLASS CORE ;
  ORIGIN 0 0 ;
  FOREIGN NOR2_X1 0 0 ;
  SYMMETRY X Y ;
  SITE i3d_nsfet3nm ;
  SIZE 0.5280 BY 0.4800 ;
  PIN VDD
    DIRECTION INOUT ;
    USE POWER ;
    PORT
      LAYER M0 ;
        RECT -0.0640 0.4560 0.5920 0.5040 ;
    END
  END VDD
  PIN VSS
    DIRECTION INOUT ;
    USE GROUND ;
    PORT
      LAYER M0 ;
        RECT -0.0640 -0.0240 0.5920 0.0240 ;
    END
  END VSS
  PIN A1
    DIRECTION INPUT ;
    USE SIGNAL ;
    PORT
      LAYER M1 ;
        RECT 0.0560 0.0640 0.1200 0.4160 ;
    END
  END A1
  PIN A2
    DIRECTION INPUT ;
    USE SIGNAL ;
    PORT
      LAYER M1 ;
        RECT 0.2320 0.0640 0.2960 0.4160 ;
    END
  END A2
  PIN ZN
    DIRECTION OUTPUT ;
    USE SIGNAL ;
    PORT
      LAYER M1 ;
        RECT 0.4080 0.0640 0.4720 0.4160 ;
    END
  END ZN
  OBS
    LAYER M0 DESIGNRULEWIDTH 0 ;
      RECT 0.0360 0.0800 0.4920 0.1200 ;
      RECT 0.0360 0.1680 0.4920 0.2160 ;
      RECT 0.0360 0.2640 0.4920 0.3120 ;
      RECT 0.0360 0.3600 0.4920 0.4000 ;
  END
END NOR2_X1

MACRO NOR2_X2
  CLASS CORE ;
  ORIGIN 0 0 ;
  FOREIGN NOR2_X2 0 0 ;
  SYMMETRY X Y ;
  SITE i3d_nsfet3nm ;
  SIZE 0.8800 BY 0.4800 ;
  PIN VDD
    DIRECTION INOUT ;
    USE POWER ;
    PORT
      LAYER M0 ;
        RECT -0.0640 0.4560 0.9440 0.5040 ;
    END
  END VDD
  PIN VSS
    DIRECTION INOUT ;
    USE GROUND ;
    PORT
      LAYER M0 ;
        RECT -0.0640 -0.0240 0.9440 0.0240 ;
    END
  END VSS
  PIN ZN
    DIRECTION OUTPUT ;
    USE SIGNAL ;
    PORT
      LAYER M1 ;
        RECT 0.5840 0.0640 0.6480 0.4160 ;
    END
  END ZN
  PIN A2
    DIRECTION INPUT ;
    USE SIGNAL ;
    PORT
      LAYER M1 ;
        RECT 0.7600 0.1600 0.8240 0.2240 ;
    END
  END A2
  PIN A1
    DIRECTION INPUT ;
    USE SIGNAL ;
    PORT
      LAYER M1 ;
        RECT 0.0560 0.1600 0.1200 0.2240 ;
    END
  END A1
  OBS
    LAYER M1 DESIGNRULEWIDTH 0 ;
      RECT 0.4080 0.2560 0.4720 0.4160 ;
      RECT 0.7600 0.3040 0.8240 0.4160 ;
      RECT 0.0560 0.3040 0.1200 0.4160 ;
    LAYER M0 DESIGNRULEWIDTH 0 ;
      RECT 0.0360 0.0800 0.8400 0.1200 ;
      RECT 0.4880 0.1680 0.8320 0.2160 ;
      RECT 0.0360 0.1680 0.3800 0.2160 ;
      RECT 0.0360 0.2640 0.8360 0.3120 ;
      RECT 0.7400 0.3600 0.8360 0.4000 ;
      RECT 0.5720 0.3600 0.6680 0.4000 ;
      RECT 0.3960 0.3600 0.4920 0.4000 ;
      RECT 0.0440 0.3600 0.1400 0.4000 ;
  END
END NOR2_X2

MACRO NOR2_X4
  CLASS CORE ;
  ORIGIN 0 0 ;
  FOREIGN NOR2_X4 0 0 ;
  SYMMETRY X Y ;
  SITE i3d_nsfet3nm ;
  SIZE 1.5840 BY 0.4800 ;
  PIN VDD
    DIRECTION INOUT ;
    USE POWER ;
    PORT
      LAYER M0 ;
        RECT -0.0640 0.4560 1.6480 0.5040 ;
    END
  END VDD
  PIN VSS
    DIRECTION INOUT ;
    USE GROUND ;
    PORT
      LAYER M0 ;
        RECT -0.0640 -0.0240 1.6480 0.0240 ;
    END
  END VSS
  PIN A2
    DIRECTION INPUT ;
    USE SIGNAL ;
    PORT
      LAYER M1 ;
        RECT 1.4640 0.1600 1.5280 0.2240 ;
    END
  END A2
  PIN ZN
    DIRECTION OUTPUT ;
    USE SIGNAL ;
    PORT
      LAYER M1 ;
        RECT 1.2880 0.0640 1.3520 0.4160 ;
    END
  END ZN
  PIN A1
    DIRECTION INPUT ;
    USE SIGNAL ;
    PORT
      LAYER M1 ;
        RECT 0.0560 0.1600 0.1200 0.2240 ;
    END
  END A1
  OBS
    LAYER M0 DESIGNRULEWIDTH 0 ;
      RECT 0.0360 0.0800 1.5400 0.1200 ;
      RECT 0.8280 0.1680 1.5360 0.2160 ;
      RECT 0.0360 0.1680 0.7280 0.2160 ;
      RECT 0.0360 0.2640 1.5360 0.3120 ;
      RECT 0.9160 0.3600 1.3720 0.4000 ;
  END
END NOR2_X4

MACRO NOR3_X1
  CLASS CORE ;
  ORIGIN 0 0 ;
  FOREIGN NOR3_X1 0 0 ;
  SYMMETRY X Y ;
  SITE i3d_nsfet3nm ;
  SIZE 0.7040 BY 0.4800 ;
  PIN VDD
    DIRECTION INOUT ;
    USE POWER ;
    PORT
      LAYER M0 ;
        RECT -0.0640 0.4560 0.7680 0.5040 ;
    END
  END VDD
  PIN VSS
    DIRECTION INOUT ;
    USE GROUND ;
    PORT
      LAYER M0 ;
        RECT -0.0640 -0.0240 0.7680 0.0240 ;
    END
  END VSS
  PIN ZN
    DIRECTION OUTPUT ;
    USE SIGNAL ;
    PORT
      LAYER M1 ;
        RECT 0.5840 0.0640 0.6480 0.4160 ;
    END
  END ZN
  PIN A1
    DIRECTION INPUT ;
    USE SIGNAL ;
    PORT
      LAYER M1 ;
        RECT 0.0560 0.2560 0.1200 0.3200 ;
    END
  END A1
  PIN A2
    DIRECTION INPUT ;
    USE SIGNAL ;
    PORT
      LAYER M1 ;
        RECT 0.2320 0.1600 0.2960 0.2240 ;
    END
  END A2
  PIN A3
    DIRECTION INPUT ;
    USE SIGNAL ;
    PORT
      LAYER M1 ;
        RECT 0.4080 0.2560 0.4720 0.3200 ;
    END
  END A3
  OBS
    LAYER M0 DESIGNRULEWIDTH 0 ;
      RECT 0.0360 0.0800 0.6640 0.1200 ;
      RECT 0.0360 0.1680 0.4920 0.2160 ;
      RECT 0.3880 0.2640 0.5680 0.3120 ;
      RECT 0.0360 0.2640 0.2160 0.3120 ;
      RECT 0.0360 0.3600 0.6600 0.4000 ;
  END
END NOR3_X1

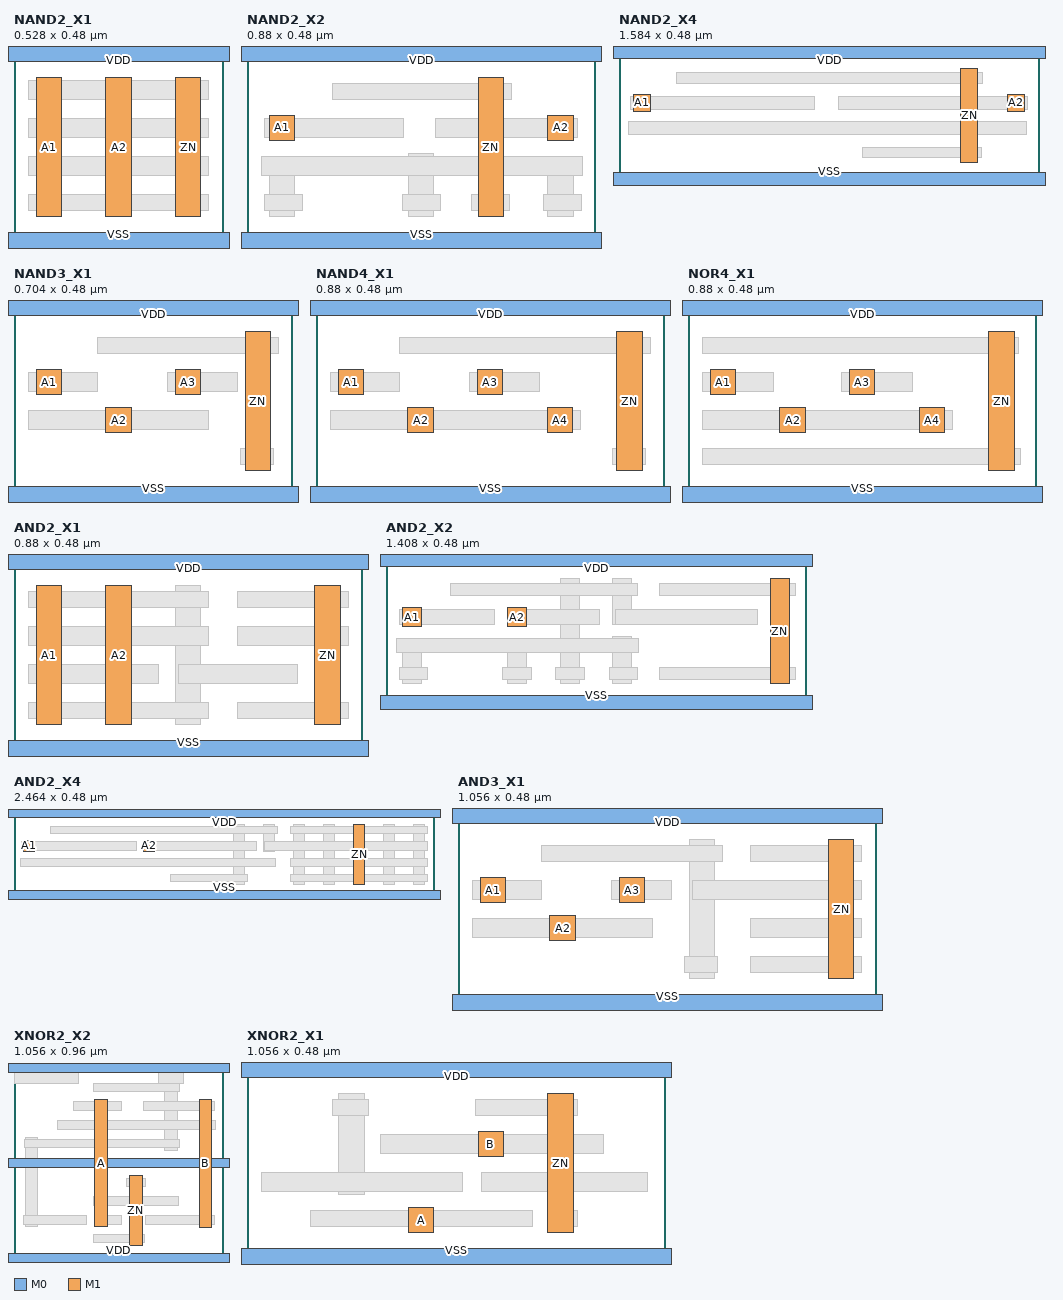
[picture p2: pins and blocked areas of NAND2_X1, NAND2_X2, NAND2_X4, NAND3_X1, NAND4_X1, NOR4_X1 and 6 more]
MACRO NAND2_X1
  CLASS CORE ;
  ORIGIN 0 0 ;
  FOREIGN NAND2_X1 0 0 ;
  SYMMETRY X Y ;
  SITE i3d_nsfet3nm ;
  SIZE 0.5280 BY 0.4800 ;
  PIN VDD
    DIRECTION INOUT ;
    USE POWER ;
    PORT
      LAYER M0 ;
        RECT -0.0640 0.4560 0.5920 0.5040 ;
    END
  END VDD
  PIN A2
    DIRECTION INPUT ;
    USE SIGNAL ;
    PORT
      LAYER M1 ;
        RECT 0.2320 0.0640 0.2960 0.4160 ;
    END
  END A2
  PIN A1
    DIRECTION INPUT ;
    USE SIGNAL ;
    PORT
      LAYER M1 ;
        RECT 0.0560 0.0640 0.1200 0.4160 ;
    END
  END A1
  PIN ZN
    DIRECTION OUTPUT ;
    USE SIGNAL ;
    PORT
      LAYER M1 ;
        RECT 0.4080 0.0640 0.4720 0.4160 ;
    END
  END ZN
  PIN VSS
    DIRECTION INOUT ;
    USE GROUND ;
    PORT
      LAYER M0 ;
        RECT -0.0640 -0.0240 0.5920 0.0240 ;
    END
  END VSS
  OBS
    LAYER M0 DESIGNRULEWIDTH 0 ;
      RECT 0.0360 0.0800 0.4920 0.1200 ;
      RECT 0.0360 0.1680 0.4920 0.2160 ;
      RECT 0.0360 0.2640 0.4920 0.3120 ;
      RECT 0.0360 0.3600 0.4920 0.4080 ;
  END
END NAND2_X1

MACRO NAND2_X2
  CLASS CORE ;
  ORIGIN 0 0 ;
  FOREIGN NAND2_X2 0 0 ;
  SYMMETRY X Y ;
  SITE i3d_nsfet3nm ;
  SIZE 0.8800 BY 0.4800 ;
  PIN VDD
    DIRECTION INOUT ;
    USE POWER ;
    PORT
      LAYER M0 ;
        RECT -0.0640 0.4560 0.9440 0.5040 ;
    END
  END VDD
  PIN VSS
    DIRECTION INOUT ;
    USE GROUND ;
    PORT
      LAYER M0 ;
        RECT -0.0640 -0.0240 0.9440 0.0240 ;
    END
  END VSS
  PIN A1
    DIRECTION INPUT ;
    USE SIGNAL ;
    PORT
      LAYER M1 ;
        RECT 0.0560 0.2560 0.1200 0.3200 ;
    END
  END A1
  PIN A2
    DIRECTION INPUT ;
    USE SIGNAL ;
    PORT
      LAYER M1 ;
        RECT 0.7600 0.2560 0.8240 0.3200 ;
    END
  END A2
  PIN ZN
    DIRECTION OUTPUT ;
    USE SIGNAL ;
    PORT
      LAYER M1 ;
        RECT 0.5840 0.0640 0.6480 0.4160 ;
    END
  END ZN
  OBS
    LAYER M1 DESIGNRULEWIDTH 0 ;
      RECT 0.7600 0.0640 0.8240 0.1760 ;
      RECT 0.4080 0.0640 0.4720 0.2240 ;
      RECT 0.0560 0.0640 0.1200 0.1760 ;
    LAYER M0 DESIGNRULEWIDTH 0 ;
      RECT 0.7480 0.0800 0.8440 0.1200 ;
      RECT 0.5680 0.0800 0.6640 0.1200 ;
      RECT 0.3920 0.0800 0.4880 0.1200 ;
      RECT 0.0440 0.0800 0.1400 0.1200 ;
      RECT 0.0360 0.1680 0.8480 0.2160 ;
      RECT 0.4760 0.2640 0.8360 0.3120 ;
      RECT 0.0440 0.2640 0.3960 0.3120 ;
      RECT 0.2160 0.3600 0.6680 0.4000 ;
  END
END NAND2_X2

MACRO NAND2_X4
  CLASS CORE ;
  ORIGIN 0 0 ;
  FOREIGN NAND2_X4 0 0 ;
  SYMMETRY X Y ;
  SITE i3d_nsfet3nm ;
  SIZE 1.5840 BY 0.4800 ;
  PIN VDD
    DIRECTION INOUT ;
    USE POWER ;
    PORT
      LAYER M0 ;
        RECT -0.0640 0.4560 1.6480 0.5040 ;
    END
  END VDD
  PIN VSS
    DIRECTION INOUT ;
    USE GROUND ;
    PORT
      LAYER M0 ;
        RECT -0.0640 -0.0240 1.6480 0.0240 ;
    END
  END VSS
  PIN A1
    DIRECTION INPUT ;
    USE SIGNAL ;
    PORT
      LAYER M1 ;
        RECT 0.0560 0.2560 0.1200 0.3200 ;
    END
  END A1
  PIN A2
    DIRECTION INPUT ;
    USE SIGNAL ;
    PORT
      LAYER M1 ;
        RECT 1.4640 0.2560 1.5280 0.3200 ;
    END
  END A2
  PIN ZN
    DIRECTION OUTPUT ;
    USE SIGNAL ;
    PORT
      LAYER M1 ;
        RECT 1.2880 0.0640 1.3520 0.4160 ;
    END
  END ZN
  OBS
    LAYER M0 DESIGNRULEWIDTH 0 ;
      RECT 0.9200 0.0800 1.3680 0.1200 ;
      RECT 0.0360 0.1680 1.5360 0.2160 ;
      RECT 0.8280 0.2640 1.5400 0.3120 ;
      RECT 0.0440 0.2640 0.7360 0.3120 ;
      RECT 0.2160 0.3600 1.3720 0.4000 ;
  END
END NAND2_X4

MACRO NAND3_X1
  CLASS CORE ;
  ORIGIN 0 0 ;
  FOREIGN NAND3_X1 0 0 ;
  SYMMETRY X Y ;
  SITE i3d_nsfet3nm ;
  SIZE 0.7040 BY 0.4800 ;
  PIN VDD
    DIRECTION INOUT ;
    USE POWER ;
    PORT
      LAYER M0 ;
        RECT -0.0640 0.4560 0.7680 0.5040 ;
    END
  END VDD
  PIN VSS
    DIRECTION INOUT ;
    USE GROUND ;
    PORT
      LAYER M0 ;
        RECT -0.0640 -0.0240 0.7680 0.0240 ;
    END
  END VSS
  PIN A1
    DIRECTION INPUT ;
    USE SIGNAL ;
    PORT
      LAYER M1 ;
        RECT 0.0560 0.2560 0.1200 0.3200 ;
    END
  END A1
  PIN A3
    DIRECTION INPUT ;
    USE SIGNAL ;
    PORT
      LAYER M1 ;
        RECT 0.4080 0.2560 0.4720 0.3200 ;
    END
  END A3
  PIN A2
    DIRECTION INPUT ;
    USE SIGNAL ;
    PORT
      LAYER M1 ;
        RECT 0.2320 0.1600 0.2960 0.2240 ;
    END
  END A2
  PIN ZN
    DIRECTION OUTPUT ;
    USE SIGNAL ;
    PORT
      LAYER M1 ;
        RECT 0.5840 0.0640 0.6480 0.4160 ;
    END
  END ZN
  OBS
    LAYER M0 DESIGNRULEWIDTH 0 ;
      RECT 0.5720 0.0800 0.6560 0.1200 ;
      RECT 0.0360 0.1680 0.4920 0.2160 ;
      RECT 0.3880 0.2640 0.5640 0.3120 ;
      RECT 0.0360 0.2640 0.2120 0.3120 ;
      RECT 0.2120 0.3600 0.6680 0.4000 ;
  END
END NAND3_X1

MACRO NAND4_X1
  CLASS CORE ;
  ORIGIN 0 0 ;
  FOREIGN NAND4_X1 0 0 ;
  SYMMETRY X Y ;
  SITE i3d_nsfet3nm ;
  SIZE 0.8800 BY 0.4800 ;
  PIN VSS
    DIRECTION INOUT ;
    USE GROUND ;
    PORT
      LAYER M0 ;
        RECT -0.0640 -0.0240 0.9440 0.0240 ;
    END
  END VSS
  PIN VDD
    DIRECTION INOUT ;
    USE POWER ;
    PORT
      LAYER M0 ;
        RECT -0.0640 0.4560 0.9440 0.5040 ;
    END
  END VDD
  PIN A1
    DIRECTION INPUT ;
    USE SIGNAL ;
    PORT
      LAYER M1 ;
        RECT 0.0560 0.2560 0.1200 0.3200 ;
    END
  END A1
  PIN A2
    DIRECTION INPUT ;
    USE SIGNAL ;
    PORT
      LAYER M1 ;
        RECT 0.2320 0.1600 0.2960 0.2240 ;
    END
  END A2
  PIN A3
    DIRECTION INPUT ;
    USE SIGNAL ;
    PORT
      LAYER M1 ;
        RECT 0.4080 0.2560 0.4720 0.3200 ;
    END
  END A3
  PIN A4
    DIRECTION INPUT ;
    USE SIGNAL ;
    PORT
      LAYER M1 ;
        RECT 0.5840 0.1600 0.6480 0.2240 ;
    END
  END A4
  PIN ZN
    DIRECTION OUTPUT ;
    USE SIGNAL ;
    PORT
      LAYER M1 ;
        RECT 0.7600 0.0640 0.8240 0.4160 ;
    END
  END ZN
  OBS
    LAYER M0 DESIGNRULEWIDTH 0 ;
      RECT 0.7480 0.0800 0.8320 0.1200 ;
      RECT 0.0360 0.1680 0.6680 0.2160 ;
      RECT 0.0360 0.2640 0.2120 0.3120 ;
      RECT 0.3880 0.2640 0.5640 0.3120 ;
      RECT 0.2120 0.3600 0.8440 0.4000 ;
  END
END NAND4_X1

MACRO NOR4_X1
  CLASS CORE ;
  ORIGIN 0 0 ;
  FOREIGN NOR4_X1 0 0 ;
  SYMMETRY X Y ;
  SITE i3d_nsfet3nm ;
  SIZE 0.8800 BY 0.4800 ;
  PIN VSS
    DIRECTION INOUT ;
    USE GROUND ;
    PORT
      LAYER M0 ;
        RECT -0.0640 -0.0240 0.9440 0.0240 ;
    END
  END VSS
  PIN VDD
    DIRECTION INOUT ;
    USE POWER ;
    PORT
      LAYER M0 ;
        RECT -0.0640 0.4560 0.9440 0.5040 ;
    END
  END VDD
  PIN A1
    DIRECTION INPUT ;
    USE SIGNAL ;
    PORT
      LAYER M1 ;
        RECT 0.0560 0.2560 0.1200 0.3200 ;
    END
  END A1
  PIN A2
    DIRECTION INPUT ;
    USE SIGNAL ;
    PORT
      LAYER M1 ;
        RECT 0.2320 0.1600 0.2960 0.2240 ;
    END
  END A2
  PIN A3
    DIRECTION INPUT ;
    USE SIGNAL ;
    PORT
      LAYER M1 ;
        RECT 0.4080 0.2560 0.4720 0.3200 ;
    END
  END A3
  PIN A4
    DIRECTION INPUT ;
    USE SIGNAL ;
    PORT
      LAYER M1 ;
        RECT 0.5840 0.1600 0.6480 0.2240 ;
    END
  END A4
  PIN ZN
    DIRECTION OUTPUT ;
    USE SIGNAL ;
    PORT
      LAYER M1 ;
        RECT 0.7600 0.0640 0.8240 0.4160 ;
    END
  END ZN
  OBS
    LAYER M0 DESIGNRULEWIDTH 0 ;
      RECT 0.0360 0.0800 0.8400 0.1200 ;
      RECT 0.0360 0.1680 0.6680 0.2160 ;
      RECT 0.0360 0.2640 0.2160 0.3120 ;
      RECT 0.3880 0.2640 0.5680 0.3120 ;
      RECT 0.0360 0.3600 0.8360 0.4000 ;
  END
END NOR4_X1

MACRO AND2_X1
  CLASS CORE ;
  ORIGIN 0 0 ;
  FOREIGN AND2_X1 0 0 ;
  SYMMETRY X Y ;
  SITE i3d_nsfet3nm ;
  SIZE 0.8800 BY 0.4800 ;
  PIN A1
    DIRECTION INPUT ;
    USE SIGNAL ;
    PORT
      LAYER M1 ;
        RECT 0.0560 0.0640 0.1200 0.4160 ;
    END
  END A1
  PIN A2
    DIRECTION INPUT ;
    USE SIGNAL ;
    PORT
      LAYER M1 ;
        RECT 0.2320 0.0640 0.2960 0.4160 ;
    END
  END A2
  PIN VDD
    DIRECTION INOUT ;
    USE POWER ;
    PORT
      LAYER M0 ;
        RECT -0.0640 0.4560 0.9440 0.5040 ;
    END
  END VDD
  PIN VSS
    DIRECTION INOUT ;
    USE GROUND ;
    PORT
      LAYER M0 ;
        RECT -0.0640 -0.0240 0.9440 0.0240 ;
    END
  END VSS
  PIN ZN
    DIRECTION OUTPUT ;
    USE SIGNAL ;
    PORT
      LAYER M1 ;
        RECT 0.7600 0.0640 0.8240 0.4160 ;
    END
  END ZN
  OBS
    LAYER M1 DESIGNRULEWIDTH 0 ;
      RECT 0.4080 0.0640 0.4720 0.4160 ;
    LAYER M0 DESIGNRULEWIDTH 0 ;
      RECT 0.5640 0.0800 0.8440 0.1200 ;
      RECT 0.0360 0.0800 0.4920 0.1200 ;
      RECT 0.4160 0.1680 0.7160 0.2160 ;
      RECT 0.0360 0.1680 0.3640 0.2160 ;
      RECT 0.5640 0.2640 0.8440 0.3120 ;
      RECT 0.0360 0.2640 0.4920 0.3120 ;
      RECT 0.5640 0.3600 0.8440 0.4000 ;
      RECT 0.0360 0.3600 0.4920 0.4000 ;
  END
END AND2_X1

MACRO AND2_X2
  CLASS CORE ;
  ORIGIN 0 0 ;
  FOREIGN AND2_X2 0 0 ;
  SYMMETRY X Y ;
  SITE i3d_nsfet3nm ;
  SIZE 1.4080 BY 0.4800 ;
  PIN A1
    DIRECTION INPUT ;
    USE SIGNAL ;
    PORT
      LAYER M1 ;
        RECT 0.0560 0.2560 0.1200 0.3200 ;
    END
  END A1
  PIN A2
    DIRECTION INPUT ;
    USE SIGNAL ;
    PORT
      LAYER M1 ;
        RECT 0.4080 0.2560 0.4720 0.3200 ;
    END
  END A2
  PIN ZN
    DIRECTION OUTPUT ;
    USE SIGNAL ;
    PORT
      LAYER M1 ;
        RECT 1.2880 0.0640 1.3520 0.4160 ;
    END
  END ZN
  PIN VDD
    DIRECTION INOUT ;
    USE POWER ;
    PORT
      LAYER M0 ;
        RECT -0.0640 0.4560 1.4720 0.5040 ;
    END
  END VDD
  PIN VSS
    DIRECTION INOUT ;
    USE GROUND ;
    PORT
      LAYER M0 ;
        RECT -0.0640 -0.0240 1.4720 0.0240 ;
    END
  END VSS
  OBS
    LAYER M1 ;
      RECT 0.7600 0.0640 0.8240 0.2240 ;
      RECT 0.5840 0.0640 0.6480 0.4160 ;
      RECT 0.4080 0.0640 0.4720 0.1760 ;
      RECT 0.0560 0.0640 0.1200 0.1760 ;
      RECT 0.7600 0.2640 0.8240 0.4160 ;
    LAYER M0 DESIGNRULEWIDTH 0 ;
      RECT 0.9160 0.0800 1.3720 0.1200 ;
      RECT 0.7480 0.0800 0.8440 0.1200 ;
      RECT 0.5680 0.0800 0.6640 0.1200 ;
      RECT 0.3920 0.0800 0.4880 0.1200 ;
      RECT 0.0440 0.0800 0.1400 0.1200 ;
      RECT 0.0360 0.1680 0.8480 0.2160 ;
      RECT 0.7680 0.2640 1.2440 0.3120 ;
      RECT 0.4160 0.2640 0.7160 0.3120 ;
      RECT 0.0440 0.2640 0.3640 0.3120 ;
      RECT 0.9160 0.3600 1.3720 0.4000 ;
      RECT 0.2160 0.3600 0.8440 0.4000 ;
  END
END AND2_X2

MACRO AND2_X4
  CLASS CORE ;
  ORIGIN 0 0 ;
  FOREIGN AND2_X4 0 0 ;
  SYMMETRY X Y ;
  SITE i3d_nsfet3nm ;
  SIZE 2.4640 BY 0.4800 ;
  PIN A1
    DIRECTION INPUT ;
    USE SIGNAL ;
    PORT
      LAYER M1 ;
        RECT 0.0560 0.2560 0.1200 0.3200 ;
    END
  END A1
  PIN A2
    DIRECTION INPUT ;
    USE SIGNAL ;
    PORT
      LAYER M1 ;
        RECT 0.7600 0.2560 0.8240 0.3200 ;
    END
  END A2
  PIN ZN
    DIRECTION OUTPUT ;
    USE SIGNAL ;
    PORT
      LAYER M1 ;
        RECT 1.9920 0.0640 2.0560 0.4160 ;
    END
  END ZN
  PIN VDD
    DIRECTION INOUT ;
    USE POWER ;
    PORT
      LAYER M0 ;
        RECT -0.0640 0.4560 2.5280 0.5040 ;
    END
  END VDD
  PIN VSS
    DIRECTION INOUT ;
    USE GROUND ;
    PORT
      LAYER M0 ;
        RECT -0.0640 -0.0240 2.5280 0.0240 ;
    END
  END VSS
  OBS
    LAYER M1 DESIGNRULEWIDTH 0 ;
      RECT 2.3440 0.0640 2.4080 0.4160 ;
      RECT 2.1680 0.0640 2.2320 0.4160 ;
      RECT 1.8160 0.0640 1.8800 0.4160 ;
      RECT 1.6400 0.0640 1.7040 0.4160 ;
      RECT 1.2880 0.0640 1.3520 0.4160 ;
      RECT 1.4640 0.2560 1.5280 0.4160 ;
    LAYER M0 DESIGNRULEWIDTH 0 ;
      RECT 1.6200 0.0800 2.4240 0.1200 ;
      RECT 0.9200 0.0800 1.3680 0.1200 ;
      RECT 1.6200 0.1680 2.4240 0.2160 ;
      RECT 0.0360 0.1680 1.5360 0.2160 ;
      RECT 1.4720 0.2640 2.4240 0.3120 ;
      RECT 0.7680 0.2640 1.4200 0.3120 ;
      RECT 0.0440 0.2640 0.7160 0.3120 ;
      RECT 1.6200 0.3600 2.4240 0.4000 ;
      RECT 0.2160 0.3600 1.5480 0.4000 ;
  END
END AND2_X4

MACRO AND3_X1
  CLASS CORE ;
  ORIGIN 0 0 ;
  FOREIGN AND3_X1 0 0 ;
  SYMMETRY X Y ;
  SITE i3d_nsfet3nm ;
  SIZE 1.0560 BY 0.4800 ;
  PIN VDD
    DIRECTION INOUT ;
    USE POWER ;
    PORT
      LAYER M0 ;
        RECT -0.0640 0.4560 1.1200 0.5040 ;
    END
  END VDD
  PIN VSS
    DIRECTION INOUT ;
    USE GROUND ;
    PORT
      LAYER M0 ;
        RECT -0.0640 -0.0240 1.1200 0.0240 ;
    END
  END VSS
  PIN A1
    DIRECTION INPUT ;
    USE SIGNAL ;
    PORT
      LAYER M1 ;
        RECT 0.0560 0.2560 0.1200 0.3200 ;
    END
  END A1
  PIN A2
    DIRECTION INPUT ;
    USE SIGNAL ;
    PORT
      LAYER M1 ;
        RECT 0.2320 0.1600 0.2960 0.2240 ;
    END
  END A2
  PIN A3
    DIRECTION INPUT ;
    USE SIGNAL ;
    PORT
      LAYER M1 ;
        RECT 0.4080 0.2560 0.4720 0.3200 ;
    END
  END A3
  PIN ZN
    DIRECTION OUTPUT ;
    USE SIGNAL ;
    PORT
      LAYER M1 ;
        RECT 0.9360 0.0640 1.0000 0.4160 ;
    END
  END ZN
  OBS
    LAYER M1 DESIGNRULEWIDTH 0 ;
      RECT 0.5840 0.0640 0.6480 0.4160 ;
    LAYER M0 DESIGNRULEWIDTH 0 ;
      RECT 0.7400 0.0800 1.0200 0.1200 ;
      RECT 0.5720 0.0800 0.6560 0.1200 ;
      RECT 0.7400 0.1680 1.0200 0.2160 ;
      RECT 0.0360 0.1680 0.4920 0.2160 ;
      RECT 0.5920 0.2640 1.0200 0.3120 ;
      RECT 0.3880 0.2640 0.5400 0.3120 ;
      RECT 0.0360 0.2640 0.2120 0.3120 ;
      RECT 0.7400 0.3600 1.0200 0.4000 ;
      RECT 0.2120 0.3600 0.6680 0.4000 ;
  END
END AND3_X1

MACRO XNOR2_X2
  CLASS CORE ;
  ORIGIN 0 0 ;
  FOREIGN XNOR2X2 0 0 ;
  SYMMETRY X Y ;
  SITE i3d_nsfet3nm_2H_VDD ;
  SIZE 1.0560 BY 0.9600 ;
  PIN VDD
    DIRECTION INOUT ;
    USE POWER ;
    PORT
      LAYER M0 ;
        RECT -0.0640 -0.0240 1.1200 0.0240 ;
        RECT -0.0640 0.9360 1.1200 0.9840 ;
    END
  END VDD
  PIN VSS
    DIRECTION INOUT ;
    USE GROUND ;
    PORT
      LAYER M0 ;
        RECT -0.0640 0.4560 1.1200 0.5040 ;
    END
  END VSS
  PIN A
    DIRECTION INPUT ;
    USE SIGNAL ;
    PORT
      LAYER M1 ;
        RECT 0.4080 0.1600 0.4720 0.8000 ;
    END
  END A
  PIN B
    DIRECTION INPUT ;
    USE SIGNAL ;
    PORT
      LAYER M1 ;
        RECT 0.9360 0.1520 1.0000 0.8000 ;
    END
  END B
  PIN ZN
    DIRECTION OUTPUT ;
    USE SIGNAL ;
    PORT
      LAYER M1 ;
        RECT 0.5840 0.0640 0.6480 0.4160 ;
    END
  END ZN
  OBS
    LAYER M1 DESIGNRULEWIDTH 0 ;
      RECT 0.0560 0.1600 0.1200 0.6080 ;
      POLYGON 0.8240 0.5440 0.8240 0.8800 0.8560 0.8800 0.8560 0.9600 0.7280 0.9600 0.7280 0.8800 0.7600 0.8800 0.7600 0.5440 ;
      RECT 0.0000 0.8800 0.3280 0.9600 ;
    LAYER M0 DESIGNRULEWIDTH 0 ;
      RECT 0.4000 0.0800 0.6600 0.1200 ;
      RECT 0.6640 0.1680 1.0120 0.2160 ;
      RECT 0.4160 0.1680 0.5440 0.2160 ;
      RECT 0.0480 0.1680 0.3680 0.2160 ;
      RECT 0.4000 0.2640 0.8320 0.3120 ;
      RECT 0.5680 0.3600 0.6640 0.4000 ;
      RECT 0.0520 0.5600 0.8360 0.6000 ;
      RECT 0.2200 0.6480 1.0160 0.6960 ;
      RECT 0.6520 0.7440 1.0120 0.7920 ;
      RECT 0.3000 0.7440 0.5440 0.7920 ;
      RECT 0.4000 0.8400 0.8360 0.8800 ;
  END
END XNOR2_X2

MACRO XNOR2_X1
  CLASS CORE ;
  ORIGIN 0 0 ;
  FOREIGN XNOR2_X1 0 0 ;
  SYMMETRY X Y ;
  SITE i3d_nsfet3nm ;
  SIZE 1.0560 BY 0.4800 ;
  PIN VDD
    DIRECTION INOUT ;
    USE POWER ;
    PORT
      LAYER M0 ;
        RECT -0.0640 0.4560 1.1200 0.5040 ;
    END
  END VDD
  PIN VSS
    DIRECTION INOUT ;
    USE GROUND ;
    PORT
      LAYER M0 ;
        RECT -0.0640 -0.0240 1.1200 0.0240 ;
    END
  END VSS
  PIN A
    DIRECTION INPUT ;
    USE SIGNAL ;
    PORT
      LAYER M1 ;
        RECT 0.4080 0.0640 0.4720 0.1280 ;
    END
  END A
  PIN B
    DIRECTION INPUT ;
    USE SIGNAL ;
    PORT
      LAYER M1 ;
        RECT 0.5840 0.2560 0.6480 0.3200 ;
    END
  END B
  PIN ZN
    DIRECTION OUTPUT ;
    USE SIGNAL ;
    PORT
      LAYER M1 ;
        RECT 0.7600 0.0640 0.8240 0.4160 ;
    END
  END ZN
  OBS
    LAYER M1 DESIGNRULEWIDTH 0 ;
      RECT 0.2320 0.1600 0.2960 0.4160 ;
    LAYER M0 DESIGNRULEWIDTH 0 ;
      RECT 0.7680 0.0800 0.8360 0.1200 ;
      RECT 0.1600 0.0800 0.7200 0.1200 ;
      RECT 0.5920 0.1680 1.0120 0.2160 ;
      RECT 0.0360 0.1680 0.5440 0.2160 ;
      RECT 0.3360 0.2640 0.9000 0.3120 ;
      RECT 0.5760 0.3600 0.8360 0.4000 ;
      RECT 0.2160 0.3600 0.3080 0.4000 ;
  END
END XNOR2_X1

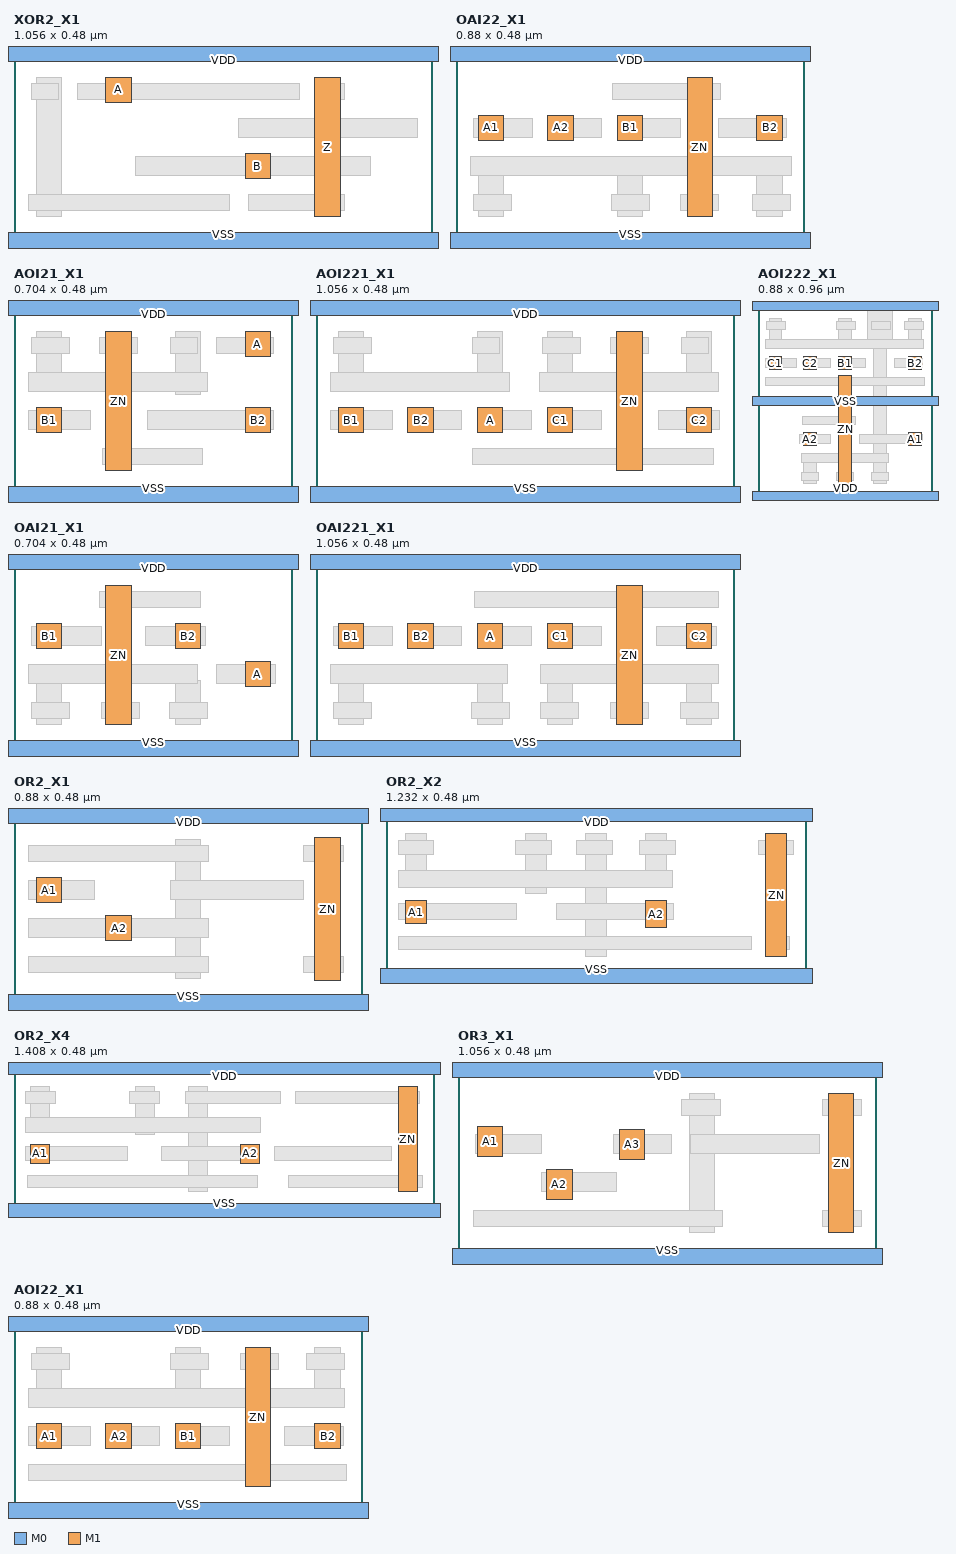
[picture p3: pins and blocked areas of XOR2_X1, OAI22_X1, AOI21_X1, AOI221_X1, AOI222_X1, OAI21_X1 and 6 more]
MACRO XOR2_X1
  CLASS CORE ;
  ORIGIN 0 0 ;
  FOREIGN XOR2_X1 0 0 ;
  SYMMETRY X Y ;
  SITE i3d_nsfet3nm ;
  SIZE 1.0560 BY 0.4800 ;
  PIN VDD
    DIRECTION INOUT ;
    USE POWER ;
    PORT
      LAYER M0 ;
        RECT -0.0640 0.4560 1.1200 0.5040 ;
    END
  END VDD
  PIN VSS
    DIRECTION INOUT ;
    USE GROUND ;
    PORT
      LAYER M0 ;
        RECT -0.0640 -0.0240 1.1200 0.0240 ;
    END
  END VSS
  PIN A
    DIRECTION INPUT ;
    USE SIGNAL ;
    PORT
      LAYER M1 ;
        RECT 0.2320 0.3520 0.2960 0.4160 ;
    END
  END A
  PIN B
    DIRECTION INPUT ;
    USE SIGNAL ;
    PORT
      LAYER M1 ;
        RECT 0.5840 0.1600 0.6480 0.2240 ;
    END
  END B
  PIN Z
    DIRECTION OUTPUT ;
    USE SIGNAL ;
    PORT
      LAYER M1 ;
        RECT 0.7600 0.0640 0.8240 0.4160 ;
    END
  END Z
  OBS
    LAYER M1 DESIGNRULEWIDTH 0 ;
      RECT 0.0560 0.0640 0.1200 0.4160 ;
    LAYER M0 DESIGNRULEWIDTH 0 ;
      RECT 0.5920 0.0800 0.8360 0.1200 ;
      RECT 0.0360 0.0800 0.5440 0.1200 ;
      RECT 0.3080 0.1680 0.9000 0.2160 ;
      RECT 0.5680 0.2640 1.0200 0.3120 ;
      RECT 0.7680 0.3600 0.8360 0.4000 ;
      RECT 0.1600 0.3600 0.7200 0.4000 ;
      RECT 0.0440 0.3600 0.1120 0.4000 ;
  END
END XOR2_X1

MACRO OAI22_X1
  CLASS CORE ;
  ORIGIN 0 0 ;
  FOREIGN OAI22_X1 0 0 ;
  SYMMETRY X Y ;
  SITE i3d_nsfet3nm ;
  SIZE 0.8800 BY 0.4800 ;
  PIN VDD
    DIRECTION INOUT ;
    USE POWER ;
    PORT
      LAYER M0 ;
        RECT -0.0640 0.4560 0.9440 0.5040 ;
    END
  END VDD
  PIN A1
    DIRECTION INPUT ;
    USE SIGNAL ;
    PORT
      LAYER M1 ;
        RECT 0.0560 0.2560 0.1200 0.3200 ;
    END
  END A1
  PIN A2
    DIRECTION INPUT ;
    USE SIGNAL ;
    PORT
      LAYER M1 ;
        RECT 0.2320 0.2560 0.2960 0.3200 ;
    END
  END A2
  PIN B1
    DIRECTION INPUT ;
    USE SIGNAL ;
    PORT
      LAYER M1 ;
        RECT 0.4080 0.2560 0.4720 0.3200 ;
    END
  END B1
  PIN ZN
    DIRECTION OUTPUT ;
    USE SIGNAL ;
    PORT
      LAYER M1 ;
        RECT 0.5840 0.0640 0.6480 0.4160 ;
    END
  END ZN
  PIN B2
    DIRECTION INPUT ;
    USE SIGNAL ;
    PORT
      LAYER M1 ;
        RECT 0.7600 0.2560 0.8240 0.3200 ;
    END
  END B2
  PIN VSS
    DIRECTION INOUT ;
    USE GROUND ;
    PORT
      LAYER M0 ;
        RECT -0.0640 -0.0240 0.9440 0.0240 ;
    END
  END VSS
  OBS
    LAYER M1 DESIGNRULEWIDTH 0 ;
      RECT 0.7600 0.0640 0.8240 0.1760 ;
      RECT 0.4080 0.0640 0.4720 0.1760 ;
      RECT 0.0560 0.0640 0.1200 0.1760 ;
    LAYER M0 DESIGNRULEWIDTH 0 ;
      RECT 0.7480 0.0800 0.8440 0.1200 ;
      RECT 0.5680 0.0800 0.6640 0.1200 ;
      RECT 0.3920 0.0800 0.4880 0.1200 ;
      RECT 0.0440 0.0800 0.1400 0.1200 ;
      RECT 0.0360 0.1680 0.8480 0.2160 ;
      RECT 0.6640 0.2640 0.8360 0.3120 ;
      RECT 0.4160 0.2640 0.5680 0.3120 ;
      RECT 0.2400 0.2640 0.3680 0.3120 ;
      RECT 0.0440 0.2640 0.1920 0.3120 ;
      RECT 0.3960 0.3600 0.6680 0.4000 ;
  END
END OAI22_X1

MACRO AOI21_X1
  CLASS CORE ;
  ORIGIN 0 0 ;
  FOREIGN AOI21_X1 0 0 ;
  SYMMETRY X Y ;
  SITE i3d_nsfet3nm ;
  SIZE 0.7040 BY 0.4800 ;
  PIN VDD
    DIRECTION INOUT ;
    USE POWER ;
    PORT
      LAYER M0 ;
        RECT -0.0640 0.4560 0.7680 0.5040 ;
    END
  END VDD
  PIN B1
    DIRECTION INPUT ;
    USE SIGNAL ;
    PORT
      LAYER M1 ;
        RECT 0.0560 0.1600 0.1200 0.2240 ;
    END
  END B1
  PIN ZN
    DIRECTION OUTPUT ;
    USE SIGNAL ;
    PORT
      LAYER M1 ;
        RECT 0.2320 0.0640 0.2960 0.4160 ;
    END
  END ZN
  PIN A
    DIRECTION INPUT ;
    USE SIGNAL ;
    PORT
      LAYER M1 ;
        RECT 0.5840 0.3520 0.6480 0.4160 ;
    END
  END A
  PIN B2
    DIRECTION INPUT ;
    USE SIGNAL ;
    PORT
      LAYER M1 ;
        RECT 0.5840 0.1600 0.6480 0.2240 ;
    END
  END B2
  PIN VSS
    DIRECTION INOUT ;
    USE GROUND ;
    PORT
      LAYER M0 ;
        RECT -0.0640 -0.0240 0.7680 0.0240 ;
    END
  END VSS
  OBS
    LAYER M1 DESIGNRULEWIDTH 0 ;
      RECT 0.4080 0.2560 0.4720 0.4160 ;
      RECT 0.0560 0.3040 0.1200 0.4160 ;
    LAYER M0 DESIGNRULEWIDTH 0 ;
      RECT 0.2240 0.0800 0.4760 0.1200 ;
      RECT 0.3360 0.1680 0.6560 0.2160 ;
      RECT 0.0360 0.1680 0.1920 0.2160 ;
      RECT 0.0360 0.2640 0.4880 0.3120 ;
      RECT 0.5120 0.3600 0.6560 0.4000 ;
      RECT 0.3960 0.3600 0.4640 0.4000 ;
      RECT 0.2160 0.3600 0.3120 0.4000 ;
      RECT 0.0440 0.3600 0.1400 0.4000 ;
  END
END AOI21_X1

MACRO AOI221_X1
  CLASS CORE ;
  ORIGIN 0 0 ;
  FOREIGN AOI221_X1 0 0 ;
  SYMMETRY X Y ;
  SITE i3d_nsfet3nm ;
  SIZE 1.0560 BY 0.4800 ;
  PIN VDD
    DIRECTION INOUT ;
    USE POWER ;
    PORT
      LAYER M0 ;
        RECT -0.0640 0.4560 1.1200 0.5040 ;
    END
  END VDD
  PIN VSS
    DIRECTION INOUT ;
    USE GROUND ;
    PORT
      LAYER M0 ;
        RECT -0.0640 -0.0240 1.1200 0.0240 ;
    END
  END VSS
  PIN B1
    DIRECTION INPUT ;
    USE SIGNAL ;
    PORT
      LAYER M1 ;
        RECT 0.0560 0.1600 0.1200 0.2240 ;
    END
  END B1
  PIN B2
    DIRECTION INPUT ;
    USE SIGNAL ;
    PORT
      LAYER M1 ;
        RECT 0.2320 0.1600 0.2960 0.2240 ;
    END
  END B2
  PIN A
    DIRECTION INPUT ;
    USE SIGNAL ;
    PORT
      LAYER M1 ;
        RECT 0.4080 0.1600 0.4720 0.2240 ;
    END
  END A
  PIN C1
    DIRECTION INPUT ;
    USE SIGNAL ;
    PORT
      LAYER M1 ;
        RECT 0.5840 0.1600 0.6480 0.2240 ;
    END
  END C1
  PIN ZN
    DIRECTION OUTPUT ;
    USE SIGNAL ;
    PORT
      LAYER M1 ;
        RECT 0.7600 0.0640 0.8240 0.4160 ;
    END
  END ZN
  PIN C2
    DIRECTION INPUT ;
    USE SIGNAL ;
    PORT
      LAYER M1 ;
        RECT 0.9360 0.1600 1.0000 0.2240 ;
    END
  END C2
  OBS
    LAYER M1 DESIGNRULEWIDTH 0 ;
      RECT 0.9360 0.3040 1.0000 0.4160 ;
      RECT 0.5840 0.3040 0.6480 0.4160 ;
      RECT 0.4080 0.3040 0.4720 0.4160 ;
      RECT 0.0560 0.3040 0.1200 0.4160 ;
    LAYER M0 DESIGNRULEWIDTH 0 ;
      RECT 0.3960 0.0800 1.0040 0.1200 ;
      RECT 0.8640 0.1680 1.0200 0.2160 ;
      RECT 0.5920 0.1680 0.7200 0.2160 ;
      RECT 0.4160 0.1680 0.5440 0.2160 ;
      RECT 0.2400 0.1680 0.3680 0.2160 ;
      RECT 0.0360 0.1680 0.1920 0.2160 ;
      RECT 0.5640 0.2640 1.0160 0.3120 ;
      RECT 0.0360 0.2640 0.4880 0.3120 ;
      RECT 0.9240 0.3600 0.9920 0.4000 ;
      RECT 0.7440 0.3600 0.8400 0.4000 ;
      RECT 0.5720 0.3600 0.6680 0.4000 ;
      RECT 0.3960 0.3600 0.4640 0.4000 ;
      RECT 0.0440 0.3600 0.1400 0.4000 ;
  END
END AOI221_X1

MACRO AOI222_X1
  CLASS CORE ;
  ORIGIN 0 0 ;
  FOREIGN AOI222_X1 0 0 ;
  SYMMETRY X Y ;
  SITE i3d_nsfet3nm_2H_VDD ;
  SIZE 0.8800 BY 0.9600 ;
  PIN VDD
    DIRECTION INOUT ;
    USE POWER ;
    PORT
      LAYER M0 ;
        RECT -0.0640 -0.0240 0.9440 0.0240 ;
        RECT -0.0640 0.9360 0.9440 0.9840 ;
    END
  END VDD
  PIN VSS
    DIRECTION INOUT ;
    USE GROUND ;
    PORT
      LAYER M0 ;
        RECT -0.0640 0.4560 0.9440 0.5040 ;
    END
  END VSS
  PIN C1
    DIRECTION INPUT ;
    USE SIGNAL ;
    PORT
      LAYER M1 ;
        RECT 0.0560 0.6400 0.1200 0.7040 ;
    END
  END C1
  PIN C2
    DIRECTION INPUT ;
    USE SIGNAL ;
    PORT
      LAYER M1 ;
        RECT 0.2320 0.6400 0.2960 0.7040 ;
    END
  END C2
  PIN B1
    DIRECTION INPUT ;
    USE SIGNAL ;
    PORT
      LAYER M1 ;
        RECT 0.4080 0.6400 0.4720 0.7040 ;
    END
  END B1
  PIN B2
    DIRECTION INPUT ;
    USE SIGNAL ;
    PORT
      LAYER M1 ;
        RECT 0.7600 0.6400 0.8240 0.7040 ;
    END
  END B2
  PIN A2
    DIRECTION INPUT ;
    USE SIGNAL ;
    PORT
      LAYER M1 ;
        RECT 0.2320 0.2560 0.2960 0.3200 ;
    END
  END A2
  PIN A1
    DIRECTION INPUT ;
    USE SIGNAL ;
    PORT
      LAYER M1 ;
        RECT 0.7600 0.2560 0.8240 0.3200 ;
    END
  END A1
  PIN ZN
    DIRECTION OUTPUT ;
    USE SIGNAL ;
    PORT
      LAYER M1 ;
        RECT 0.4080 0.0640 0.4720 0.6080 ;
    END
  END ZN
  OBS
    LAYER M1 DESIGNRULEWIDTH 0 ;
      POLYGON 0.6480 0.0640 0.6480 0.7840 0.6800 0.7840 0.6800 0.9600 0.5520 0.9600 0.5520 0.7840 0.5840 0.7840 0.5840 0.0640 ;
      RECT 0.2320 0.0640 0.2960 0.1760 ;
      RECT 0.7600 0.7840 0.8240 0.8960 ;
      RECT 0.4080 0.7840 0.4720 0.8960 ;
      RECT 0.0560 0.7840 0.1200 0.8960 ;
    LAYER M0 DESIGNRULEWIDTH 0 ;
      RECT 0.5720 0.0800 0.6600 0.1200 ;
      RECT 0.3960 0.0800 0.4840 0.1200 ;
      RECT 0.2200 0.0800 0.3080 0.1200 ;
      RECT 0.2200 0.1680 0.6600 0.2160 ;
      RECT 0.5120 0.2640 0.8320 0.3120 ;
      RECT 0.2120 0.2640 0.3680 0.3120 ;
      RECT 0.2240 0.3600 0.4920 0.4000 ;
      RECT 0.0360 0.5600 0.8400 0.6000 ;
      RECT 0.6880 0.6480 0.8320 0.6960 ;
      RECT 0.4160 0.6480 0.5440 0.6960 ;
      RECT 0.2400 0.6480 0.3680 0.6960 ;
      RECT 0.0360 0.6480 0.1920 0.6960 ;
      RECT 0.0360 0.7440 0.8360 0.7920 ;
      RECT 0.7400 0.8400 0.8360 0.8800 ;
      RECT 0.5720 0.8400 0.6680 0.8800 ;
      RECT 0.3960 0.8400 0.4920 0.8800 ;
      RECT 0.0440 0.8400 0.1400 0.8800 ;
  END
END AOI222_X1

MACRO OAI21_X1
  CLASS CORE ;
  ORIGIN 0 0 ;
  FOREIGN OAI21_X1 0 0 ;
  SYMMETRY X Y ;
  SITE i3d_nsfet3nm ;
  SIZE 0.7040 BY 0.4800 ;
  PIN VDD
    DIRECTION INOUT ;
    USE POWER ;
    PORT
      LAYER M0 ;
        RECT -0.0640 0.4560 0.7680 0.5040 ;
    END
  END VDD
  PIN VSS
    DIRECTION INOUT ;
    USE GROUND ;
    PORT
      LAYER M0 ;
        RECT -0.0640 -0.0240 0.7680 0.0240 ;
    END
  END VSS
  PIN B1
    DIRECTION INPUT ;
    USE SIGNAL ;
    PORT
      LAYER M1 ;
        RECT 0.0560 0.2560 0.1200 0.3200 ;
    END
  END B1
  PIN ZN
    DIRECTION OUTPUT ;
    USE SIGNAL ;
    PORT
      LAYER M1 ;
        RECT 0.2320 0.0640 0.2960 0.4160 ;
    END
  END ZN
  PIN B2
    DIRECTION INPUT ;
    USE SIGNAL ;
    PORT
      LAYER M1 ;
        RECT 0.4080 0.2560 0.4720 0.3200 ;
    END
  END B2
  PIN A
    DIRECTION INPUT ;
    USE SIGNAL ;
    PORT
      LAYER M1 ;
        RECT 0.5840 0.1600 0.6480 0.2240 ;
    END
  END A
  OBS
    LAYER M1 DESIGNRULEWIDTH 0 ;
      RECT 0.4080 0.0640 0.4720 0.1760 ;
      RECT 0.0560 0.0640 0.1200 0.1760 ;
    LAYER M0 DESIGNRULEWIDTH 0 ;
      RECT 0.3920 0.0800 0.4880 0.1200 ;
      RECT 0.2200 0.0800 0.3160 0.1200 ;
      RECT 0.0440 0.0800 0.1400 0.1200 ;
      RECT 0.5120 0.1680 0.6600 0.2160 ;
      RECT 0.0360 0.1680 0.4640 0.2160 ;
      RECT 0.3320 0.2640 0.4840 0.3120 ;
      RECT 0.0440 0.2640 0.2200 0.3120 ;
      RECT 0.2160 0.3600 0.4720 0.4000 ;
  END
END OAI21_X1

MACRO OAI221_X1
  CLASS CORE ;
  ORIGIN 0 0 ;
  FOREIGN OAI221_X1 0 0 ;
  SYMMETRY X Y ;
  SITE i3d_nsfet3nm ;
  SIZE 1.0560 BY 0.4800 ;
  PIN VDD
    DIRECTION INOUT ;
    USE POWER ;
    PORT
      LAYER M0 ;
        RECT -0.0640 0.4560 1.1200 0.5040 ;
    END
  END VDD
  PIN VSS
    DIRECTION INOUT ;
    USE GROUND ;
    PORT
      LAYER M0 ;
        RECT -0.0640 -0.0240 1.1200 0.0240 ;
    END
  END VSS
  PIN B1
    DIRECTION INPUT ;
    USE SIGNAL ;
    PORT
      LAYER M1 ;
        RECT 0.0560 0.2560 0.1200 0.3200 ;
    END
  END B1
  PIN B2
    DIRECTION INPUT ;
    USE SIGNAL ;
    PORT
      LAYER M1 ;
        RECT 0.2320 0.2560 0.2960 0.3200 ;
    END
  END B2
  PIN A
    DIRECTION INPUT ;
    USE SIGNAL ;
    PORT
      LAYER M1 ;
        RECT 0.4080 0.2560 0.4720 0.3200 ;
    END
  END A
  PIN C1
    DIRECTION INPUT ;
    USE SIGNAL ;
    PORT
      LAYER M1 ;
        RECT 0.5840 0.2560 0.6480 0.3200 ;
    END
  END C1
  PIN ZN
    DIRECTION OUTPUT ;
    USE SIGNAL ;
    PORT
      LAYER M1 ;
        RECT 0.7600 0.0640 0.8240 0.4160 ;
    END
  END ZN
  PIN C2
    DIRECTION INPUT ;
    USE SIGNAL ;
    PORT
      LAYER M1 ;
        RECT 0.9360 0.2560 1.0000 0.3200 ;
    END
  END C2
  OBS
    LAYER M1 DESIGNRULEWIDTH 0 ;
      RECT 0.9360 0.0640 1.0000 0.1760 ;
      RECT 0.5840 0.0640 0.6480 0.1760 ;
      RECT 0.4080 0.0640 0.4720 0.1760 ;
      RECT 0.0560 0.0640 0.1200 0.1760 ;
    LAYER M0 DESIGNRULEWIDTH 0 ;
      RECT 0.9200 0.0800 1.0160 0.1200 ;
      RECT 0.7440 0.0800 0.8400 0.1200 ;
      RECT 0.5680 0.0800 0.6640 0.1200 ;
      RECT 0.3920 0.0800 0.4880 0.1200 ;
      RECT 0.0440 0.0800 0.1400 0.1200 ;
      RECT 0.5680 0.1680 1.0160 0.2160 ;
      RECT 0.0360 0.1680 0.4840 0.2160 ;
      RECT 0.8600 0.2640 1.0120 0.3120 ;
      RECT 0.5920 0.2640 0.7200 0.3120 ;
      RECT 0.4160 0.2640 0.5440 0.3120 ;
      RECT 0.2400 0.2640 0.3680 0.3120 ;
      RECT 0.0440 0.2640 0.1920 0.3120 ;
      RECT 0.4000 0.3600 1.0160 0.4000 ;
  END
END OAI221_X1

MACRO OR2_X1
  CLASS CORE ;
  ORIGIN 0 0 ;
  FOREIGN OR2_X1 0 0 ;
  SYMMETRY X Y ;
  SITE i3d_nsfet3nm ;
  SIZE 0.8800 BY 0.4800 ;
  PIN VDD
    DIRECTION INOUT ;
    USE POWER ;
    PORT
      LAYER M0 ;
        RECT -0.0640 0.4560 0.9440 0.5040 ;
    END
  END VDD
  PIN VSS
    DIRECTION INOUT ;
    USE GROUND ;
    PORT
      LAYER M0 ;
        RECT -0.0640 -0.0240 0.9440 0.0240 ;
    END
  END VSS
  PIN A1
    DIRECTION INPUT ;
    USE SIGNAL ;
    PORT
      LAYER M1 ;
        RECT 0.0560 0.2560 0.1200 0.3200 ;
    END
  END A1
  PIN ZN
    DIRECTION OUTPUT ;
    USE SIGNAL ;
    PORT
      LAYER M1 ;
        RECT 0.7600 0.0600 0.8240 0.4200 ;
    END
  END ZN
  PIN A2
    DIRECTION INPUT ;
    USE SIGNAL ;
    PORT
      LAYER M1 ;
        RECT 0.2320 0.1600 0.2960 0.2240 ;
    END
  END A2
  OBS
    LAYER M1 DESIGNRULEWIDTH 0 ;
      RECT 0.4080 0.0640 0.4720 0.4160 ;
    LAYER M0 DESIGNRULEWIDTH 0 ;
      RECT 0.7320 0.0800 0.8320 0.1200 ;
      RECT 0.0360 0.0800 0.4920 0.1200 ;
      RECT 0.0360 0.1680 0.4920 0.2160 ;
      RECT 0.3960 0.2640 0.7320 0.3120 ;
      RECT 0.0360 0.2640 0.2040 0.3120 ;
      RECT 0.7320 0.3600 0.8320 0.4000 ;
      RECT 0.0360 0.3600 0.4920 0.4000 ;
  END
END OR2_X1

MACRO OR2_X2
  CLASS CORE ;
  ORIGIN 0 0 ;
  FOREIGN OR2_X2 0 0 ;
  SYMMETRY X Y ;
  SITE i3d_nsfet3nm ;
  SIZE 1.2320 BY 0.4800 ;
  PIN VDD
    DIRECTION INOUT ;
    USE POWER ;
    PORT
      LAYER M0 ;
        RECT -0.0640 0.4560 1.2960 0.5040 ;
    END
  END VDD
  PIN VSS
    DIRECTION INOUT ;
    USE GROUND ;
    PORT
      LAYER M0 ;
        RECT -0.0640 -0.0240 1.2960 0.0240 ;
    END
  END VSS
  PIN A1
    DIRECTION INPUT ;
    USE SIGNAL ;
    PORT
      LAYER M1 ;
        RECT 0.0560 0.1560 0.1200 0.2240 ;
    END
  END A1
  PIN A2
    DIRECTION INPUT ;
    USE SIGNAL ;
    PORT
      LAYER M1 ;
        RECT 0.7600 0.1440 0.8240 0.2240 ;
    END
  END A2
  PIN ZN
    DIRECTION OUTPUT ;
    USE SIGNAL ;
    PORT
      LAYER M1 ;
        RECT 1.1120 0.0600 1.1760 0.4200 ;
    END
  END ZN
  OBS
    LAYER M1 DESIGNRULEWIDTH 0 ;
      RECT 0.5840 0.0600 0.6480 0.4200 ;
      RECT 0.4080 0.2440 0.4720 0.4200 ;
      RECT 0.7600 0.3040 0.8240 0.4200 ;
      RECT 0.0560 0.3040 0.1200 0.4200 ;
    LAYER M0 DESIGNRULEWIDTH 0 ;
      RECT 1.1200 0.0800 1.1840 0.1200 ;
      RECT 0.0360 0.0800 1.0720 0.1200 ;
      RECT 0.5000 0.1680 0.8440 0.2160 ;
      RECT 0.0360 0.1680 0.3840 0.2160 ;
      RECT 0.0360 0.2640 0.8400 0.3120 ;
      RECT 1.0920 0.3600 1.1960 0.4000 ;
      RECT 0.7440 0.3600 0.8480 0.4000 ;
      RECT 0.5600 0.3600 0.6640 0.4000 ;
      RECT 0.3800 0.3600 0.4840 0.4000 ;
      RECT 0.0360 0.3600 0.1400 0.4000 ;
  END
END OR2_X2

MACRO OR2_X4
  CLASS CORE ;
  ORIGIN 0 0 ;
  FOREIGN OR2_X4 0 0 ;
  SYMMETRY X Y ;
  SITE i3d_nsfet3nm ;
  SIZE 1.4080 BY 0.4800 ;
  PIN VDD
    DIRECTION INOUT ;
    USE POWER ;
    PORT
      LAYER M0 ;
        RECT -0.0640 0.4560 1.4720 0.5040 ;
    END
  END VDD
  PIN VSS
    DIRECTION INOUT ;
    USE GROUND ;
    PORT
      LAYER M0 ;
        RECT -0.0640 -0.0240 1.4720 0.0240 ;
    END
  END VSS
  PIN A1
    DIRECTION INPUT ;
    USE SIGNAL ;
    PORT
      LAYER M1 ;
        RECT 0.0560 0.1600 0.1200 0.2240 ;
    END
  END A1
  PIN A2
    DIRECTION INPUT ;
    USE SIGNAL ;
    PORT
      LAYER M1 ;
        RECT 0.7600 0.1600 0.8240 0.2240 ;
    END
  END A2
  PIN ZN
    DIRECTION OUTPUT ;
    USE SIGNAL ;
    PORT
      LAYER M1 ;
        RECT 1.2880 0.0640 1.3520 0.4160 ;
    END
  END ZN
  OBS
    LAYER M1 DESIGNRULEWIDTH 0 ;
      RECT 0.5840 0.0640 0.6480 0.4160 ;
      RECT 0.4080 0.2560 0.4720 0.4160 ;
      RECT 0.0560 0.3040 0.1200 0.4160 ;
    LAYER M0 DESIGNRULEWIDTH 0 ;
      RECT 0.9200 0.0800 1.3680 0.1200 ;
      RECT 0.0440 0.0800 0.8160 0.1200 ;
      RECT 0.8720 0.1680 1.2640 0.2160 ;
      RECT 0.4960 0.1680 0.8200 0.2160 ;
      RECT 0.0400 0.1680 0.3800 0.2160 ;
      RECT 0.0400 0.2640 0.8280 0.3120 ;
      RECT 0.9440 0.3600 1.3600 0.4000 ;
      RECT 0.5760 0.3600 0.8920 0.4000 ;
      RECT 0.3880 0.3600 0.4880 0.4000 ;
      RECT 0.0400 0.3600 0.1400 0.4000 ;
  END
END OR2_X4

MACRO OR3_X1
  CLASS CORE ;
  ORIGIN 0 0 ;
  FOREIGN OR3_X1 0 0 ;
  SYMMETRY X Y ;
  SITE i3d_nsfet3nm ;
  SIZE 1.0560 BY 0.4800 ;
  PIN VDD
    DIRECTION INOUT ;
    USE POWER ;
    PORT
      LAYER M0 ;
        RECT -0.0640 0.4560 1.1200 0.5040 ;
    END
  END VDD
  PIN VSS
    DIRECTION INOUT ;
    USE GROUND ;
    PORT
      LAYER M0 ;
        RECT -0.0640 -0.0240 1.1200 0.0240 ;
    END
  END VSS
  PIN A1
    DIRECTION INPUT ;
    USE SIGNAL ;
    PORT
      LAYER M1 ;
        RECT 0.0480 0.2560 0.1120 0.3320 ;
    END
  END A1
  PIN A2
    DIRECTION INPUT ;
    USE SIGNAL ;
    PORT
      LAYER M1 ;
        RECT 0.2240 0.1480 0.2880 0.2240 ;
    END
  END A2
  PIN A3
    DIRECTION INPUT ;
    USE SIGNAL ;
    PORT
      LAYER M1 ;
        RECT 0.4080 0.2480 0.4720 0.3240 ;
    END
  END A3
  PIN ZN
    DIRECTION OUTPUT ;
    USE SIGNAL ;
    PORT
      LAYER M1 ;
        RECT 0.9360 0.0640 1.0000 0.4160 ;
    END
  END ZN
  OBS
    LAYER M1 DESIGNRULEWIDTH 0 ;
      RECT 0.5840 0.0640 0.6480 0.4160 ;
    LAYER M0 DESIGNRULEWIDTH 0 ;
      RECT 0.9200 0.0800 1.0200 0.1200 ;
      RECT 0.0400 0.0800 0.6680 0.1200 ;
      RECT 0.2120 0.1680 0.4000 0.2160 ;
      RECT 0.5880 0.2640 0.9120 0.3120 ;
      RECT 0.3920 0.2640 0.5400 0.3120 ;
      RECT 0.0440 0.2640 0.2120 0.3120 ;
      RECT 0.9200 0.3600 1.0200 0.4000 ;
      RECT 0.5640 0.3600 0.6640 0.4000 ;
  END
END OR3_X1

MACRO AOI22_X1
  CLASS CORE ;
  ORIGIN 0 0 ;
  FOREIGN AOI22_X1 0 0 ;
  SYMMETRY X Y ;
  SITE i3d_nsfet3nm ;
  SIZE 0.8800 BY 0.4800 ;
  PIN VDD
    DIRECTION INOUT ;
    USE POWER ;
    PORT
      LAYER M0 ;
        RECT -0.0640 0.4560 0.9440 0.5040 ;
    END
  END VDD
  PIN VSS
    DIRECTION INOUT ;
    USE GROUND ;
    PORT
      LAYER M0 ;
        RECT -0.0640 -0.0240 0.9440 0.0240 ;
    END
  END VSS
  PIN A1
    DIRECTION INPUT ;
    USE SIGNAL ;
    PORT
      LAYER M1 ;
        RECT 0.0560 0.1600 0.1200 0.2240 ;
    END
  END A1
  PIN A2
    DIRECTION INPUT ;
    USE SIGNAL ;
    PORT
      LAYER M1 ;
        RECT 0.2320 0.1600 0.2960 0.2240 ;
    END
  END A2
  PIN B1
    DIRECTION INPUT ;
    USE SIGNAL ;
    PORT
      LAYER M1 ;
        RECT 0.4080 0.1600 0.4720 0.2240 ;
    END
  END B1
  PIN ZN
    DIRECTION OUTPUT ;
    USE SIGNAL ;
    PORT
      LAYER M1 ;
        RECT 0.5840 0.0640 0.6480 0.4160 ;
    END
  END ZN
  PIN B2
    DIRECTION INPUT ;
    USE SIGNAL ;
    PORT
      LAYER M1 ;
        RECT 0.7600 0.1600 0.8240 0.2240 ;
    END
  END B2
  OBS
    LAYER M1 DESIGNRULEWIDTH 0 ;
      RECT 0.7600 0.3040 0.8240 0.4160 ;
      RECT 0.4080 0.3040 0.4720 0.4160 ;
      RECT 0.0560 0.3040 0.1200 0.4160 ;
    LAYER M0 DESIGNRULEWIDTH 0 ;
      RECT 0.0360 0.0800 0.8400 0.1200 ;
      RECT 0.6840 0.1680 0.8320 0.2160 ;
      RECT 0.4160 0.1680 0.5440 0.2160 ;
      RECT 0.2400 0.1680 0.3680 0.2160 ;
      RECT 0.0360 0.1680 0.1920 0.2160 ;
      RECT 0.0360 0.2640 0.8360 0.3120 ;
      RECT 0.7400 0.3600 0.8360 0.4000 ;
      RECT 0.5720 0.3600 0.6680 0.4000 ;
      RECT 0.3960 0.3600 0.4920 0.4000 ;
      RECT 0.0440 0.3600 0.1400 0.4000 ;
  END
END AOI22_X1

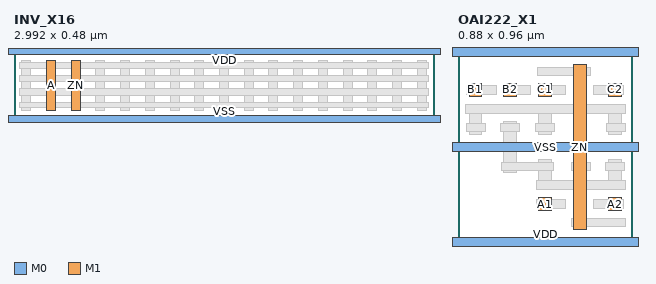
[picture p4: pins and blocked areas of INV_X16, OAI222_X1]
MACRO INV_X16
  CLASS CORE ;
  ORIGIN 0 0 ;
  FOREIGN INV_X16 0 0 ;
  SYMMETRY X Y ;
  SITE i3d_nsfet3nm ;
  SIZE 2.9920 BY 0.4800 ;
  PIN VDD
    DIRECTION INOUT ;
    USE POWER ;
    PORT
      LAYER M0 ;
        RECT -0.0640 0.4560 3.0560 0.5040 ;
    END
  END VDD
  PIN VSS
    DIRECTION INOUT ;
    USE GROUND ;
    PORT
      LAYER M0 ;
        RECT -0.0640 -0.0240 3.0560 0.0240 ;
    END
  END VSS
  PIN A
    DIRECTION INPUT ;
    USE SIGNAL ;
    PORT
      LAYER M1 ;
        RECT 0.2320 0.0640 0.2960 0.4160 ;
    END
  END A
  PIN ZN
    DIRECTION OUTPUT ;
    USE SIGNAL ;
    PORT
      LAYER M1 ;
        RECT 0.4080 0.0640 0.4720 0.4160 ;
    END
  END ZN
  OBS
    LAYER M1 DESIGNRULEWIDTH 0 ;
      RECT 2.8720 0.0640 2.9360 0.4160 ;
      RECT 2.6960 0.0640 2.7600 0.4160 ;
      RECT 2.5200 0.0640 2.5840 0.4160 ;
      RECT 2.3440 0.0640 2.4080 0.4160 ;
      RECT 2.1680 0.0640 2.2320 0.4160 ;
      RECT 1.9920 0.0640 2.0560 0.4160 ;
      RECT 1.8160 0.0640 1.8800 0.4160 ;
      RECT 1.6400 0.0640 1.7040 0.4160 ;
      RECT 1.4640 0.0640 1.5280 0.4160 ;
      RECT 1.2880 0.0640 1.3520 0.4160 ;
      RECT 1.1120 0.0640 1.1760 0.4160 ;
      RECT 0.9360 0.0640 1.0000 0.4160 ;
      RECT 0.7600 0.0640 0.8240 0.4160 ;
      RECT 0.5840 0.0640 0.6480 0.4160 ;
      RECT 0.0560 0.0640 0.1200 0.4160 ;
    LAYER M0 DESIGNRULEWIDTH 0 ;
      RECT 0.0360 0.0800 2.9520 0.1200 ;
      RECT 0.0360 0.1680 2.9520 0.2160 ;
      RECT 0.0360 0.2640 2.9520 0.3120 ;
      RECT 0.0360 0.3600 2.9520 0.4000 ;
  END
END INV_X16

MACRO OAI222_X1
  CLASS CORE ;
  ORIGIN 0 0 ;
  FOREIGN OAI222_X1 0 0 ;
  SYMMETRY X Y ;
  SITE i3d_nsfet3nm_2H_VDD ;
  SIZE 0.8800 BY 0.9600 ;
  PIN VDD
    DIRECTION INOUT ;
    USE POWER ;
    PORT
      LAYER M0 ;
        RECT -0.0640 -0.0240 0.9440 0.0240 ;
        RECT -0.0640 0.9360 0.9440 0.9840 ;
    END
  END VDD
  PIN VSS
    DIRECTION INOUT ;
    USE GROUND ;
    PORT
      LAYER M0 ;
        RECT -0.0640 0.4560 0.9440 0.5040 ;
    END
  END VSS
  PIN B1
    DIRECTION INPUT ;
    USE SIGNAL ;
    PORT
      LAYER M1 ;
        RECT 0.0560 0.7360 0.1200 0.8000 ;
    END
  END B1
  PIN B2
    DIRECTION INPUT ;
    USE SIGNAL ;
    PORT
      LAYER M1 ;
        RECT 0.2320 0.7360 0.2960 0.8000 ;
    END
  END B2
  PIN C1
    DIRECTION INPUT ;
    USE SIGNAL ;
    PORT
      LAYER M1 ;
        RECT 0.4080 0.7360 0.4720 0.8000 ;
    END
  END C1
  PIN ZN
    DIRECTION OUTPUT ;
    USE SIGNAL ;
    PORT
      LAYER M1 ;
        RECT 0.5840 0.0640 0.6480 0.8960 ;
    END
  END ZN
  PIN C2
    DIRECTION INPUT ;
    USE SIGNAL ;
    PORT
      LAYER M1 ;
        RECT 0.7600 0.7360 0.8240 0.8000 ;
    END
  END C2
  PIN A1
    DIRECTION INPUT ;
    USE SIGNAL ;
    PORT
      LAYER M1 ;
        RECT 0.4080 0.1600 0.4720 0.2240 ;
    END
  END A1
  PIN A2
    DIRECTION INPUT ;
    USE SIGNAL ;
    PORT
      LAYER M1 ;
        RECT 0.7600 0.1600 0.8240 0.2240 ;
    END
  END A2
  OBS
    LAYER M1 DESIGNRULEWIDTH 0 ;
      RECT 0.7600 0.3040 0.8240 0.4160 ;
      RECT 0.4080 0.3040 0.4720 0.4160 ;
      RECT 0.2320 0.3520 0.2960 0.6080 ;
      RECT 0.7600 0.5440 0.8240 0.6560 ;
      RECT 0.4080 0.5440 0.4720 0.6560 ;
      RECT 0.0560 0.5440 0.1200 0.6560 ;
    LAYER M0 DESIGNRULEWIDTH 0 ;
      RECT 0.5720 0.0800 0.8440 0.1200 ;
      RECT 0.6840 0.1680 0.8360 0.2160 ;
      RECT 0.3960 0.1680 0.5440 0.2160 ;
      RECT 0.3960 0.2640 0.8480 0.3120 ;
      RECT 0.7440 0.3600 0.8400 0.4000 ;
      RECT 0.5720 0.3600 0.6680 0.4000 ;
      RECT 0.2200 0.3600 0.4840 0.4000 ;
      RECT 0.7480 0.5600 0.8440 0.6000 ;
      RECT 0.3920 0.5600 0.4880 0.6000 ;
      RECT 0.2160 0.5600 0.3120 0.6000 ;
      RECT 0.0440 0.5600 0.1400 0.6000 ;
      RECT 0.0360 0.6480 0.8480 0.6960 ;
      RECT 0.6840 0.7440 0.8360 0.7920 ;
      RECT 0.4160 0.7440 0.5440 0.7920 ;
      RECT 0.2400 0.7440 0.3680 0.7920 ;
      RECT 0.0440 0.7440 0.1920 0.7920 ;
      RECT 0.4040 0.8400 0.6680 0.8800 ;
  END
END OAI222_X1

END LIBRARY
